VERSION 5.8 ;
BUSBITCHARS "[]" ;
DIVIDERCHAR "/" ;
CLEARANCEMEASURE EUCLIDEAN ;

SITE gt2_7t
    SIZE 0.0420 BY 0.1680 ;
    CLASS CORE ;
    SYMMETRY Y ;
END gt2_7t

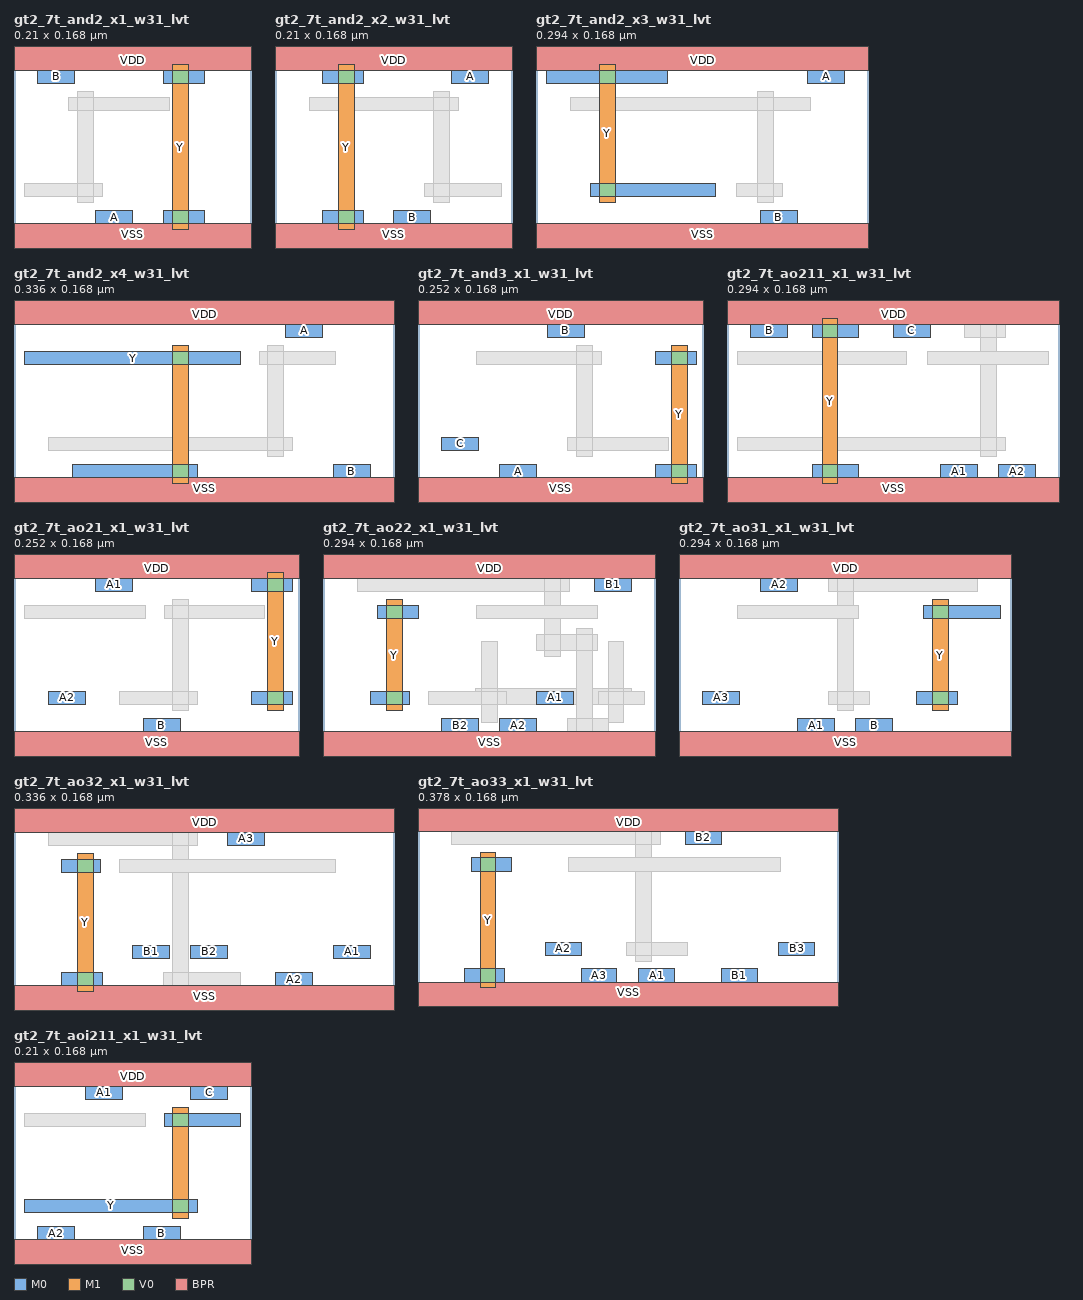
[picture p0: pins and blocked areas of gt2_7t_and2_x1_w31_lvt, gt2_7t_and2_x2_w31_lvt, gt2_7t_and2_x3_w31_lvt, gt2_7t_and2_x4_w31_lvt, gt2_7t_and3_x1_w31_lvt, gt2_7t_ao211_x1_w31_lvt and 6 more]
MACRO gt2_7t_and2_x1_w31_lvt
  CLASS CORE ;
  ORIGIN 0 0 ;
  FOREIGN gt2_6t_and2_x1_w31_lvt 0 0 ;
  SIZE 0.2100 BY 0.1680 ;
  SYMMETRY X Y ;
  SITE gt2_7t ;
  PIN A
    DIRECTION INPUT ;
    USE SIGNAL ;
    PORT
      LAYER M0 ;
        RECT 0.0725 0.0160 0.1050 0.0280 ;
    END
  END A
  PIN B
    DIRECTION INPUT ;
    USE SIGNAL ;
    PORT
      LAYER M0 ;
        RECT 0.0210 0.1400 0.0535 0.1520 ;
    END
  END B
  PIN Y
    DIRECTION OUTPUT ;
    USE SIGNAL ;
    PORT
      LAYER M1 ;
        RECT 0.1400 0.0110 0.1540 0.1570 ;
      LAYER M0 ;
        RECT 0.1320 0.0160 0.1680 0.0280 ;
        RECT 0.1320 0.1400 0.1680 0.1520 ;
      LAYER V0 ;
        RECT 0.1400 0.0160 0.1540 0.0280 ;
        RECT 0.1400 0.1400 0.1540 0.1520 ;
    END
  END Y
  PIN VDD
    DIRECTION INOUT ;
    USE POWER ;
    SHAPE ABUTMENT ;
    PORT
      LAYER BPR ;
        RECT 0.0000 0.1520 0.2100 0.1840 ;
    END
  END VDD
  PIN VSS
    DIRECTION INOUT ;
    USE GROUND ;
    SHAPE ABUTMENT ;
    PORT
      LAYER BPR ;
        RECT 0.0000 -0.0160 0.2100 0.0160 ;
    END
  END VSS
  OBS
    LAYER M1 ;
      RECT 0.0560 0.0350 0.0700 0.1330 ;
    LAYER M0 ;
      RECT 0.0095 0.0400 0.0780 0.0520 ;
      RECT 0.0480 0.1160 0.1375 0.1280 ;
    LAYER V0 ;
      RECT 0.0560 0.0400 0.0700 0.0520 ;
      RECT 0.0560 0.1160 0.0700 0.1280 ;
  END
END gt2_7t_and2_x1_w31_lvt

MACRO gt2_7t_and2_x2_w31_lvt
  CLASS CORE ;
  ORIGIN 0 0 ;
  FOREIGN gt2_6t_and2_x2_w31_lvt 0 0 ;
  SIZE 0.2100 BY 0.1680 ;
  SYMMETRY X Y ;
  SITE gt2_7t ;
  PIN A
    DIRECTION INPUT ;
    USE SIGNAL ;
    PORT
      LAYER M0 ;
        RECT 0.1565 0.1400 0.1890 0.1520 ;
    END
  END A
  PIN B
    DIRECTION INPUT ;
    USE SIGNAL ;
    PORT
      LAYER M0 ;
        RECT 0.1050 0.0160 0.1375 0.0280 ;
    END
  END B
  PIN Y
    DIRECTION OUTPUT ;
    USE SIGNAL ;
    PORT
      LAYER M1 ;
        RECT 0.0560 0.0110 0.0700 0.1570 ;
      LAYER M0 ;
        RECT 0.0420 0.0160 0.0780 0.0280 ;
        RECT 0.0420 0.1400 0.0780 0.1520 ;
      LAYER V0 ;
        RECT 0.0560 0.0160 0.0700 0.0280 ;
        RECT 0.0560 0.1400 0.0700 0.1520 ;
    END
  END Y
  PIN VDD
    DIRECTION INOUT ;
    USE POWER ;
    SHAPE ABUTMENT ;
    PORT
      LAYER BPR ;
        RECT 0.0000 0.1520 0.2100 0.1840 ;
    END
  END VDD
  PIN VSS
    DIRECTION INOUT ;
    USE GROUND ;
    SHAPE ABUTMENT ;
    PORT
      LAYER BPR ;
        RECT 0.0000 -0.0160 0.2100 0.0160 ;
    END
  END VSS
  OBS
    LAYER M1 ;
      RECT 0.1400 0.0350 0.1540 0.1330 ;
    LAYER M0 ;
      RECT 0.1320 0.0400 0.2005 0.0520 ;
      RECT 0.0305 0.1160 0.1620 0.1280 ;
    LAYER V0 ;
      RECT 0.1400 0.0400 0.1540 0.0520 ;
      RECT 0.1400 0.1160 0.1540 0.1280 ;
  END
END gt2_7t_and2_x2_w31_lvt

MACRO gt2_7t_and2_x3_w31_lvt
  CLASS CORE ;
  ORIGIN 0 0 ;
  FOREIGN gt2_6t_and2_x3_w31_lvt 0 0 ;
  SIZE 0.2940 BY 0.1680 ;
  SYMMETRY X Y ;
  SITE gt2_7t ;
  PIN A
    DIRECTION INPUT ;
    USE SIGNAL ;
    PORT
      LAYER M0 ;
        RECT 0.2405 0.1400 0.2730 0.1520 ;
    END
  END A
  PIN B
    DIRECTION INPUT ;
    USE SIGNAL ;
    PORT
      LAYER M0 ;
        RECT 0.1985 0.0160 0.2310 0.0280 ;
    END
  END B
  PIN Y
    DIRECTION OUTPUT ;
    USE SIGNAL ;
    PORT
      LAYER M1 ;
        RECT 0.0560 0.0350 0.0700 0.1570 ;
      LAYER M0 ;
        RECT 0.0480 0.0400 0.1585 0.0520 ;
        RECT 0.0095 0.1400 0.1165 0.1520 ;
      LAYER V0 ;
        RECT 0.0560 0.0400 0.0700 0.0520 ;
        RECT 0.0560 0.1400 0.0700 0.1520 ;
    END
  END Y
  PIN VDD
    DIRECTION INOUT ;
    USE POWER ;
    SHAPE ABUTMENT ;
    PORT
      LAYER BPR ;
        RECT 0.0000 0.1520 0.2940 0.1840 ;
    END
  END VDD
  PIN VSS
    DIRECTION INOUT ;
    USE GROUND ;
    SHAPE ABUTMENT ;
    PORT
      LAYER BPR ;
        RECT 0.0000 -0.0160 0.2940 0.0160 ;
    END
  END VSS
  OBS
    LAYER M1 ;
      RECT 0.1960 0.0350 0.2100 0.1330 ;
    LAYER M0 ;
      RECT 0.1775 0.0400 0.2180 0.0520 ;
      RECT 0.0305 0.1160 0.2425 0.1280 ;
    LAYER V0 ;
      RECT 0.1960 0.0400 0.2100 0.0520 ;
      RECT 0.1960 0.1160 0.2100 0.1280 ;
  END
END gt2_7t_and2_x3_w31_lvt

MACRO gt2_7t_and2_x4_w31_lvt
  CLASS CORE ;
  ORIGIN 0 0 ;
  FOREIGN gt2_6t_and2_x4_w31_lvt 0 0 ;
  SIZE 0.3360 BY 0.1680 ;
  SYMMETRY X Y ;
  SITE gt2_7t ;
  PIN A
    DIRECTION INPUT ;
    USE SIGNAL ;
    PORT
      LAYER M0 ;
        RECT 0.2405 0.1400 0.2730 0.1520 ;
    END
  END A
  PIN B
    DIRECTION INPUT ;
    USE SIGNAL ;
    PORT
      LAYER M0 ;
        RECT 0.2825 0.0160 0.3150 0.0280 ;
    END
  END B
  PIN Y
    DIRECTION OUTPUT ;
    USE SIGNAL ;
    PORT
      LAYER M1 ;
        RECT 0.1400 0.0110 0.1540 0.1330 ;
      LAYER M0 ;
        RECT 0.0515 0.0160 0.1620 0.0280 ;
        RECT 0.0095 0.1160 0.2005 0.1280 ;
      LAYER V0 ;
        RECT 0.1400 0.0160 0.1540 0.0280 ;
        RECT 0.1400 0.1160 0.1540 0.1280 ;
    END
  END Y
  PIN VDD
    DIRECTION INOUT ;
    USE POWER ;
    SHAPE ABUTMENT ;
    PORT
      LAYER BPR ;
        RECT 0.0000 0.1520 0.3360 0.1840 ;
    END
  END VDD
  PIN VSS
    DIRECTION INOUT ;
    USE GROUND ;
    SHAPE ABUTMENT ;
    PORT
      LAYER BPR ;
        RECT 0.0000 -0.0160 0.3360 0.0160 ;
    END
  END VSS
  OBS
    LAYER M1 ;
      RECT 0.2240 0.0350 0.2380 0.1330 ;
    LAYER M0 ;
      RECT 0.0305 0.0400 0.2460 0.0520 ;
      RECT 0.2175 0.1160 0.2845 0.1280 ;
    LAYER V0 ;
      RECT 0.2240 0.0400 0.2380 0.0520 ;
      RECT 0.2240 0.1160 0.2380 0.1280 ;
  END
END gt2_7t_and2_x4_w31_lvt

MACRO gt2_7t_and3_x1_w31_lvt
  CLASS CORE ;
  ORIGIN 0 0 ;
  FOREIGN gt2_6t_and3_x1_w31_lvt 0 0 ;
  SIZE 0.2520 BY 0.1680 ;
  SYMMETRY X Y ;
  SITE gt2_7t ;
  PIN A
    DIRECTION INPUT ;
    USE SIGNAL ;
    PORT
      LAYER M0 ;
        RECT 0.0725 0.0160 0.1050 0.0280 ;
    END
  END A
  PIN B
    DIRECTION INPUT ;
    USE SIGNAL ;
    PORT
      LAYER M0 ;
        RECT 0.1145 0.1400 0.1470 0.1520 ;
    END
  END B
  PIN C
    DIRECTION INPUT ;
    USE SIGNAL ;
    PORT
      LAYER M0 ;
        RECT 0.0210 0.0400 0.0535 0.0520 ;
    END
  END C
  PIN Y
    DIRECTION OUTPUT ;
    USE SIGNAL ;
    PORT
      LAYER M1 ;
        RECT 0.2240 0.0110 0.2380 0.1330 ;
      LAYER M0 ;
        RECT 0.2100 0.0160 0.2460 0.0280 ;
        RECT 0.2100 0.1160 0.2460 0.1280 ;
      LAYER V0 ;
        RECT 0.2240 0.0160 0.2380 0.0280 ;
        RECT 0.2240 0.1160 0.2380 0.1280 ;
    END
  END Y
  PIN VDD
    DIRECTION INOUT ;
    USE POWER ;
    SHAPE ABUTMENT ;
    PORT
      LAYER BPR ;
        RECT 0.0000 0.1520 0.2520 0.1840 ;
    END
  END VDD
  PIN VSS
    DIRECTION INOUT ;
    USE GROUND ;
    SHAPE ABUTMENT ;
    PORT
      LAYER BPR ;
        RECT 0.0000 -0.0160 0.2520 0.0160 ;
    END
  END VSS
  OBS
    LAYER M1 ;
      RECT 0.1400 0.0350 0.1540 0.1330 ;
    LAYER M0 ;
      RECT 0.1320 0.0400 0.2215 0.0520 ;
      RECT 0.0515 0.1160 0.1620 0.1280 ;
    LAYER V0 ;
      RECT 0.1400 0.0400 0.1540 0.0520 ;
      RECT 0.1400 0.1160 0.1540 0.1280 ;
  END
END gt2_7t_and3_x1_w31_lvt

MACRO gt2_7t_ao211_x1_w31_lvt
  CLASS CORE ;
  ORIGIN 0 0 ;
  FOREIGN gt2_6t_ao211_x1_w31_lvt 0 0 ;
  SIZE 0.2940 BY 0.1680 ;
  SYMMETRY X Y ;
  SITE gt2_7t ;
  PIN A1
    DIRECTION INPUT ;
    USE SIGNAL ;
    PORT
      LAYER M0 ;
        RECT 0.1890 0.0160 0.2215 0.0280 ;
    END
  END A1
  PIN A2
    DIRECTION INPUT ;
    USE SIGNAL ;
    PORT
      LAYER M0 ;
        RECT 0.2405 0.0160 0.2730 0.0280 ;
    END
  END A2
  PIN B
    DIRECTION INPUT ;
    USE SIGNAL ;
    PORT
      LAYER M0 ;
        RECT 0.0210 0.1400 0.0535 0.1520 ;
    END
  END B
  PIN C
    DIRECTION INPUT ;
    USE SIGNAL ;
    PORT
      LAYER M0 ;
        RECT 0.1470 0.1400 0.1795 0.1520 ;
    END
  END C
  PIN Y
    DIRECTION OUTPUT ;
    USE SIGNAL ;
    PORT
      LAYER M1 ;
        RECT 0.0840 0.0110 0.0980 0.1570 ;
      LAYER M0 ;
        RECT 0.0760 0.0160 0.1165 0.0280 ;
        RECT 0.0760 0.1400 0.1165 0.1520 ;
      LAYER V0 ;
        RECT 0.0840 0.0160 0.0980 0.0280 ;
        RECT 0.0840 0.1400 0.0980 0.1520 ;
    END
  END Y
  PIN VDD
    DIRECTION INOUT ;
    USE POWER ;
    SHAPE ABUTMENT ;
    PORT
      LAYER BPR ;
        RECT 0.0000 0.1520 0.2940 0.1840 ;
    END
  END VDD
  PIN VSS
    DIRECTION INOUT ;
    USE GROUND ;
    SHAPE ABUTMENT ;
    PORT
      LAYER BPR ;
        RECT 0.0000 -0.0160 0.2940 0.0160 ;
    END
  END VSS
  OBS
    LAYER M1 ;
      RECT 0.2240 0.0350 0.2380 0.1570 ;
    LAYER M0 ;
      RECT 0.0095 0.0400 0.2460 0.0520 ;
      RECT 0.2100 0.1400 0.2460 0.1520 ;
      RECT 0.0095 0.1160 0.1585 0.1280 ;
      RECT 0.1775 0.1160 0.2845 0.1280 ;
    LAYER V0 ;
      RECT 0.2240 0.0400 0.2380 0.0520 ;
      RECT 0.2240 0.1400 0.2380 0.1520 ;
  END
END gt2_7t_ao211_x1_w31_lvt

MACRO gt2_7t_ao21_x1_w31_lvt
  CLASS CORE ;
  ORIGIN 0 0 ;
  FOREIGN gt2_6t_ao21_x1_w31_lvt 0 0 ;
  SIZE 0.2520 BY 0.1680 ;
  SYMMETRY X Y ;
  SITE gt2_7t ;
  PIN A1
    DIRECTION INPUT ;
    USE SIGNAL ;
    PORT
      LAYER M0 ;
        RECT 0.0725 0.1400 0.1050 0.1520 ;
    END
  END A1
  PIN A2
    DIRECTION INPUT ;
    USE SIGNAL ;
    PORT
      LAYER M0 ;
        RECT 0.0305 0.0400 0.0630 0.0520 ;
    END
  END A2
  PIN B
    DIRECTION INPUT ;
    USE SIGNAL ;
    PORT
      LAYER M0 ;
        RECT 0.1145 0.0160 0.1470 0.0280 ;
    END
  END B
  PIN Y
    DIRECTION OUTPUT ;
    USE SIGNAL ;
    PORT
      LAYER M1 ;
        RECT 0.2240 0.0350 0.2380 0.1570 ;
      LAYER M0 ;
        RECT 0.2100 0.0400 0.2460 0.0520 ;
        RECT 0.2100 0.1400 0.2460 0.1520 ;
      LAYER V0 ;
        RECT 0.2240 0.0400 0.2380 0.0520 ;
        RECT 0.2240 0.1400 0.2380 0.1520 ;
    END
  END Y
  PIN VDD
    DIRECTION INOUT ;
    USE POWER ;
    SHAPE ABUTMENT ;
    PORT
      LAYER BPR ;
        RECT 0.0000 0.1520 0.2520 0.1840 ;
    END
  END VDD
  PIN VSS
    DIRECTION INOUT ;
    USE GROUND ;
    SHAPE ABUTMENT ;
    PORT
      LAYER BPR ;
        RECT 0.0000 -0.0160 0.2520 0.0160 ;
    END
  END VSS
  OBS
    LAYER M1 ;
      RECT 0.1400 0.0350 0.1540 0.1330 ;
    LAYER M0 ;
      RECT 0.0095 0.1160 0.1165 0.1280 ;
      RECT 0.0935 0.0400 0.1620 0.0520 ;
      RECT 0.1335 0.1160 0.2215 0.1280 ;
    LAYER V0 ;
      RECT 0.1400 0.0400 0.1540 0.0520 ;
      RECT 0.1400 0.1160 0.1540 0.1280 ;
  END
END gt2_7t_ao21_x1_w31_lvt

MACRO gt2_7t_ao22_x1_w31_lvt
  CLASS CORE ;
  ORIGIN 0 0 ;
  FOREIGN gt2_6t_ao22_x1_w31_lvt 0 0 ;
  SIZE 0.2940 BY 0.1680 ;
  SYMMETRY X Y ;
  SITE gt2_7t ;
  PIN A1
    DIRECTION INPUT ;
    USE SIGNAL ;
    PORT
      LAYER M0 ;
        RECT 0.1890 0.0400 0.2215 0.0520 ;
    END
  END A1
  PIN A2
    DIRECTION INPUT ;
    USE SIGNAL ;
    PORT
      LAYER M0 ;
        RECT 0.1565 0.0160 0.1890 0.0280 ;
    END
  END A2
  PIN B1
    DIRECTION INPUT ;
    USE SIGNAL ;
    PORT
      LAYER M0 ;
        RECT 0.2405 0.1400 0.2730 0.1520 ;
    END
  END B1
  PIN B2
    DIRECTION INPUT ;
    USE SIGNAL ;
    PORT
      LAYER M0 ;
        RECT 0.1050 0.0160 0.1375 0.0280 ;
    END
  END B2
  PIN Y
    DIRECTION OUTPUT ;
    USE SIGNAL ;
    PORT
      LAYER M1 ;
        RECT 0.0560 0.0350 0.0700 0.1330 ;
      LAYER M0 ;
        RECT 0.0420 0.0400 0.0765 0.0520 ;
        RECT 0.0480 0.1160 0.0840 0.1280 ;
      LAYER V0 ;
        RECT 0.0560 0.0400 0.0700 0.0520 ;
        RECT 0.0560 0.1160 0.0700 0.1280 ;
    END
  END Y
  PIN VDD
    DIRECTION INOUT ;
    USE POWER ;
    SHAPE ABUTMENT ;
    PORT
      LAYER BPR ;
        RECT 0.0000 0.1520 0.2940 0.1840 ;
    END
  END VDD
  PIN VSS
    DIRECTION INOUT ;
    USE GROUND ;
    SHAPE ABUTMENT ;
    PORT
      LAYER BPR ;
        RECT 0.0000 -0.0160 0.2940 0.0160 ;
    END
  END VSS
  OBS
    LAYER M2 ;
      RECT 0.1890 0.0880 0.2430 0.1020 ;
      RECT 0.1350 0.0400 0.2730 0.0540 ;
    LAYER M1 ;
      RECT 0.2240 0.0110 0.2380 0.1070 ;
      RECT 0.1960 0.0830 0.2100 0.1570 ;
      RECT 0.1400 0.0240 0.1540 0.0960 ;
      RECT 0.2520 0.0240 0.2660 0.0960 ;
    LAYER M0 ;
      RECT 0.2160 0.0160 0.2520 0.0280 ;
      RECT 0.0305 0.1400 0.2180 0.1520 ;
      RECT 0.0935 0.0400 0.1620 0.0520 ;
      RECT 0.2440 0.0400 0.2845 0.0520 ;
      RECT 0.1355 0.1160 0.2425 0.1280 ;
    LAYER V1 ;
      RECT 0.1960 0.0880 0.2100 0.1020 ;
      RECT 0.2240 0.0880 0.2380 0.1020 ;
      RECT 0.1400 0.0400 0.1540 0.0540 ;
      RECT 0.2520 0.0400 0.2660 0.0540 ;
    LAYER V0 ;
      RECT 0.2240 0.0160 0.2380 0.0280 ;
      RECT 0.1960 0.1400 0.2100 0.1520 ;
      RECT 0.1400 0.0400 0.1540 0.0520 ;
      RECT 0.2520 0.0400 0.2660 0.0520 ;
  END
END gt2_7t_ao22_x1_w31_lvt

MACRO gt2_7t_ao31_x1_w31_lvt
  CLASS CORE ;
  ORIGIN 0 0 ;
  FOREIGN gt2_6t_ao31_x1_w31_lvt 0 0 ;
  SIZE 0.2940 BY 0.1680 ;
  SYMMETRY X Y ;
  SITE gt2_7t ;
  PIN A1
    DIRECTION INPUT ;
    USE SIGNAL ;
    PORT
      LAYER M0 ;
        RECT 0.1050 0.0160 0.1375 0.0280 ;
    END
  END A1
  PIN A2
    DIRECTION INPUT ;
    USE SIGNAL ;
    PORT
      LAYER M0 ;
        RECT 0.0725 0.1400 0.1050 0.1520 ;
    END
  END A2
  PIN A3
    DIRECTION INPUT ;
    USE SIGNAL ;
    PORT
      LAYER M0 ;
        RECT 0.0210 0.0400 0.0535 0.0520 ;
    END
  END A3
  PIN B
    DIRECTION INPUT ;
    USE SIGNAL ;
    PORT
      LAYER M0 ;
        RECT 0.1565 0.0160 0.1890 0.0280 ;
    END
  END B
  PIN Y
    DIRECTION OUTPUT ;
    USE SIGNAL ;
    PORT
      LAYER M1 ;
        RECT 0.2240 0.0350 0.2380 0.1330 ;
      LAYER M0 ;
        RECT 0.2100 0.0400 0.2460 0.0520 ;
        RECT 0.2160 0.1160 0.2845 0.1280 ;
      LAYER V0 ;
        RECT 0.2240 0.0400 0.2380 0.0520 ;
        RECT 0.2240 0.1160 0.2380 0.1280 ;
    END
  END Y
  PIN VDD
    DIRECTION INOUT ;
    USE POWER ;
    SHAPE ABUTMENT ;
    PORT
      LAYER BPR ;
        RECT 0.0000 0.1520 0.2940 0.1840 ;
    END
  END VDD
  PIN VSS
    DIRECTION INOUT ;
    USE GROUND ;
    SHAPE ABUTMENT ;
    PORT
      LAYER BPR ;
        RECT 0.0000 -0.0160 0.2940 0.0160 ;
    END
  END VSS
  OBS
    LAYER M1 ;
      RECT 0.1400 0.0350 0.1540 0.1570 ;
    LAYER M0 ;
      RECT 0.0515 0.1160 0.1585 0.1280 ;
      RECT 0.1320 0.0400 0.1680 0.0520 ;
      RECT 0.1320 0.1400 0.2635 0.1520 ;
    LAYER V0 ;
      RECT 0.1400 0.0400 0.1540 0.0520 ;
      RECT 0.1400 0.1400 0.1540 0.1520 ;
  END
END gt2_7t_ao31_x1_w31_lvt

MACRO gt2_7t_ao32_x1_w31_lvt
  CLASS CORE ;
  ORIGIN 0 0 ;
  FOREIGN gt2_6t_ao32_x1_w31_lvt 0 0 ;
  SIZE 0.3360 BY 0.1680 ;
  SYMMETRY X Y ;
  SITE gt2_7t ;
  PIN A1
    DIRECTION INPUT ;
    USE SIGNAL ;
    PORT
      LAYER M0 ;
        RECT 0.2825 0.0400 0.3150 0.0520 ;
    END
  END A1
  PIN A2
    DIRECTION INPUT ;
    USE SIGNAL ;
    PORT
      LAYER M0 ;
        RECT 0.2310 0.0160 0.2635 0.0280 ;
    END
  END A2
  PIN A3
    DIRECTION INPUT ;
    USE SIGNAL ;
    PORT
      LAYER M0 ;
        RECT 0.1890 0.1400 0.2215 0.1520 ;
    END
  END A3
  PIN B1
    DIRECTION INPUT ;
    USE SIGNAL ;
    PORT
      LAYER M0 ;
        RECT 0.1050 0.0400 0.1375 0.0520 ;
    END
  END B1
  PIN B2
    DIRECTION INPUT ;
    USE SIGNAL ;
    PORT
      LAYER M0 ;
        RECT 0.1565 0.0400 0.1890 0.0520 ;
    END
  END B2
  PIN Y
    DIRECTION OUTPUT ;
    USE SIGNAL ;
    PORT
      LAYER M1 ;
        RECT 0.0560 0.0110 0.0700 0.1330 ;
      LAYER M0 ;
        RECT 0.0420 0.0160 0.0780 0.0280 ;
        RECT 0.0420 0.1160 0.0765 0.1280 ;
      LAYER V0 ;
        RECT 0.0560 0.0160 0.0700 0.0280 ;
        RECT 0.0560 0.1160 0.0700 0.1280 ;
    END
  END Y
  PIN VDD
    DIRECTION INOUT ;
    USE POWER ;
    SHAPE ABUTMENT ;
    PORT
      LAYER BPR ;
        RECT 0.0000 0.1520 0.3360 0.1840 ;
    END
  END VDD
  PIN VSS
    DIRECTION INOUT ;
    USE GROUND ;
    SHAPE ABUTMENT ;
    PORT
      LAYER BPR ;
        RECT 0.0000 -0.0160 0.3360 0.0160 ;
    END
  END VSS
  OBS
    LAYER M1 ;
      RECT 0.1400 0.0110 0.1540 0.1570 ;
    LAYER M0 ;
      RECT 0.1320 0.0160 0.2005 0.0280 ;
      RECT 0.0305 0.1400 0.1620 0.1520 ;
      RECT 0.0935 0.1160 0.2845 0.1280 ;
    LAYER V0 ;
      RECT 0.1400 0.0160 0.1540 0.0280 ;
      RECT 0.1400 0.1400 0.1540 0.1520 ;
  END
END gt2_7t_ao32_x1_w31_lvt

MACRO gt2_7t_ao33_x1_w31_lvt
  CLASS CORE ;
  ORIGIN 0 0 ;
  FOREIGN gt2_6t_ao33_x1_w31_lvt 0 0 ;
  SIZE 0.3780 BY 0.1680 ;
  SYMMETRY X Y ;
  SITE gt2_7t ;
  PIN A1
    DIRECTION INPUT ;
    USE SIGNAL ;
    PORT
      LAYER M0 ;
        RECT 0.1985 0.0160 0.2310 0.0280 ;
    END
  END A1
  PIN A2
    DIRECTION INPUT ;
    USE SIGNAL ;
    PORT
      LAYER M0 ;
        RECT 0.1145 0.0400 0.1470 0.0520 ;
    END
  END A2
  PIN A3
    DIRECTION INPUT ;
    USE SIGNAL ;
    PORT
      LAYER M0 ;
        RECT 0.1470 0.0160 0.1790 0.0280 ;
    END
  END A3
  PIN B1
    DIRECTION INPUT ;
    USE SIGNAL ;
    PORT
      LAYER M0 ;
        RECT 0.2730 0.0160 0.3055 0.0280 ;
    END
  END B1
  PIN B2
    DIRECTION INPUT ;
    USE SIGNAL ;
    PORT
      LAYER M0 ;
        RECT 0.2405 0.1400 0.2730 0.1520 ;
    END
  END B2
  PIN B3
    DIRECTION INPUT ;
    USE SIGNAL ;
    PORT
      LAYER M0 ;
        RECT 0.3245 0.0400 0.3570 0.0520 ;
    END
  END B3
  PIN Y
    DIRECTION OUTPUT ;
    USE SIGNAL ;
    PORT
      LAYER M1 ;
        RECT 0.0560 0.0110 0.0700 0.1330 ;
      LAYER M0 ;
        RECT 0.0420 0.0160 0.0780 0.0280 ;
        RECT 0.0480 0.1160 0.0840 0.1280 ;
      LAYER V0 ;
        RECT 0.0560 0.0160 0.0700 0.0280 ;
        RECT 0.0560 0.1160 0.0700 0.1280 ;
    END
  END Y
  PIN VDD
    DIRECTION INOUT ;
    USE POWER ;
    SHAPE ABUTMENT ;
    PORT
      LAYER BPR ;
        RECT 0.0000 0.1520 0.3780 0.1840 ;
    END
  END VDD
  PIN VSS
    DIRECTION INOUT ;
    USE GROUND ;
    SHAPE ABUTMENT ;
    PORT
      LAYER BPR ;
        RECT 0.0000 -0.0160 0.3780 0.0160 ;
    END
  END VSS
  OBS
    LAYER M1 ;
      RECT 0.1960 0.0350 0.2100 0.1570 ;
    LAYER M0 ;
      RECT 0.1355 0.1160 0.3265 0.1280 ;
      RECT 0.1880 0.0400 0.2425 0.0520 ;
      RECT 0.0305 0.1400 0.2180 0.1520 ;
    LAYER V0 ;
      RECT 0.1960 0.0400 0.2100 0.0520 ;
      RECT 0.1960 0.1400 0.2100 0.1520 ;
  END
END gt2_7t_ao33_x1_w31_lvt

MACRO gt2_7t_aoi211_x1_w31_lvt
  CLASS CORE ;
  ORIGIN 0 0 ;
  FOREIGN gt2_6t_aoi211_x1_w31_lvt 0 0 ;
  SIZE 0.2100 BY 0.1680 ;
  SYMMETRY X Y ;
  SITE gt2_7t ;
  PIN A1
    DIRECTION INPUT ;
    USE SIGNAL ;
    PORT
      LAYER M0 ;
        RECT 0.0630 0.1400 0.0955 0.1520 ;
    END
  END A1
  PIN A2
    DIRECTION INPUT ;
    USE SIGNAL ;
    PORT
      LAYER M0 ;
        RECT 0.0210 0.0160 0.0535 0.0280 ;
    END
  END A2
  PIN B
    DIRECTION INPUT ;
    USE SIGNAL ;
    PORT
      LAYER M0 ;
        RECT 0.1145 0.0160 0.1470 0.0280 ;
    END
  END B
  PIN C
    DIRECTION INPUT ;
    USE SIGNAL ;
    PORT
      LAYER M0 ;
        RECT 0.1565 0.1400 0.1890 0.1520 ;
    END
  END C
  PIN Y
    DIRECTION OUTPUT ;
    USE SIGNAL ;
    PORT
      LAYER M1 ;
        RECT 0.1400 0.0350 0.1540 0.1330 ;
      LAYER M0 ;
        RECT 0.0095 0.0400 0.1620 0.0520 ;
        RECT 0.1335 0.1160 0.2005 0.1280 ;
      LAYER V0 ;
        RECT 0.1400 0.0400 0.1540 0.0520 ;
        RECT 0.1400 0.1160 0.1540 0.1280 ;
    END
  END Y
  PIN VDD
    DIRECTION INOUT ;
    USE POWER ;
    SHAPE ABUTMENT ;
    PORT
      LAYER BPR ;
        RECT 0.0000 0.1520 0.2100 0.1840 ;
    END
  END VDD
  PIN VSS
    DIRECTION INOUT ;
    USE GROUND ;
    SHAPE ABUTMENT ;
    PORT
      LAYER BPR ;
        RECT 0.0000 -0.0160 0.2100 0.0160 ;
    END
  END VSS
  OBS
    LAYER M0 ;
      RECT 0.0095 0.1160 0.1165 0.1280 ;
  END
END gt2_7t_aoi211_x1_w31_lvt

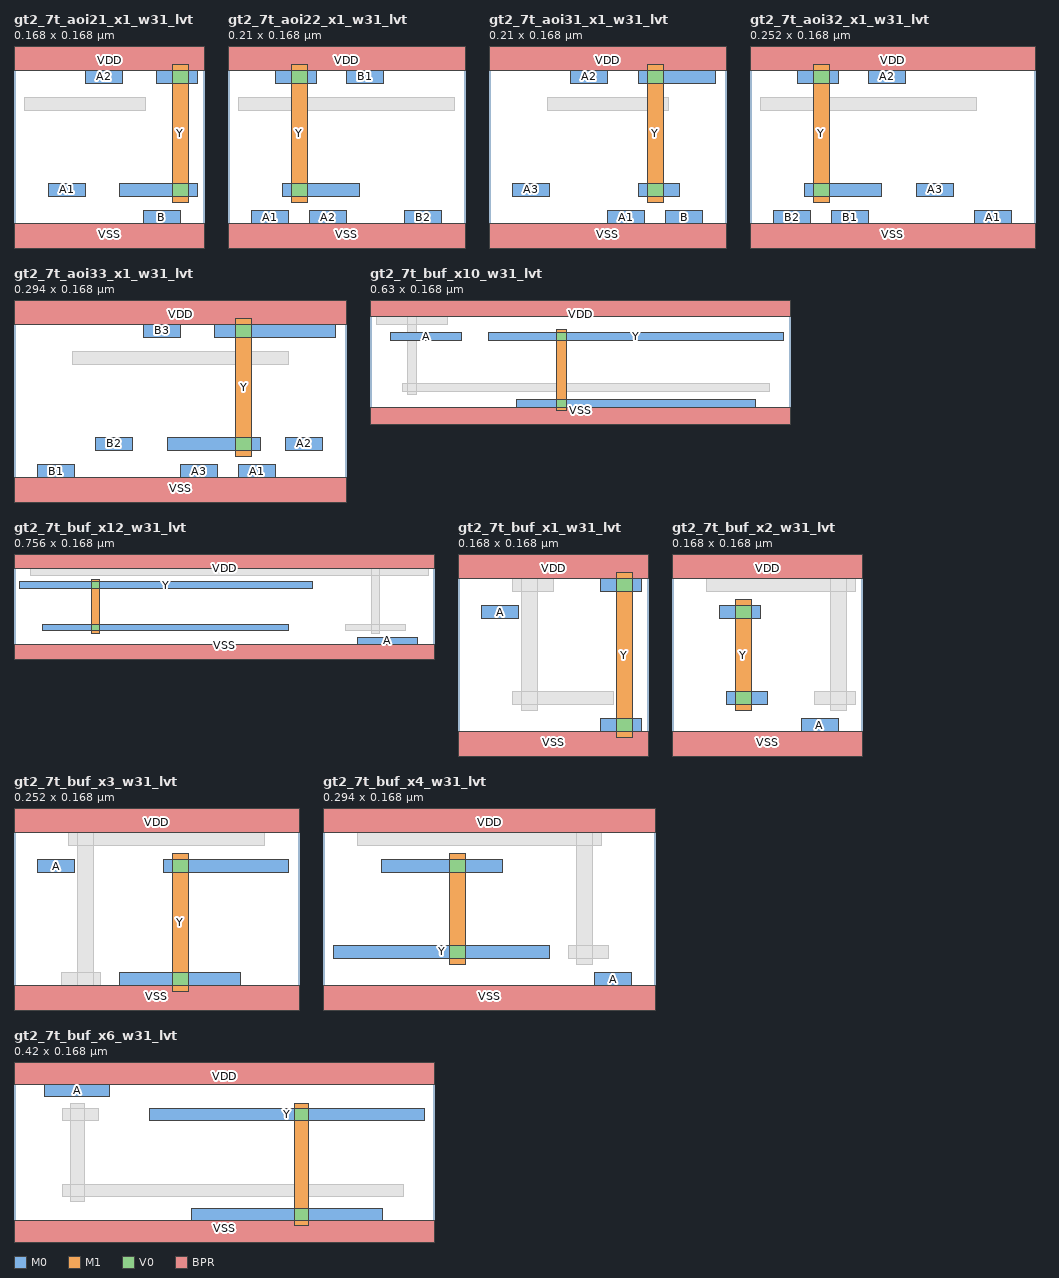
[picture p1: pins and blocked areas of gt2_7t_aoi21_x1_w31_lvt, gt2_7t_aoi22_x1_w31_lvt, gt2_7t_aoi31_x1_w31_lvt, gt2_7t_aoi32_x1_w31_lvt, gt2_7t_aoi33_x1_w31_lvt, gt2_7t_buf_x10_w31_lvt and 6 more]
MACRO gt2_7t_aoi21_x1_w31_lvt
  CLASS CORE ;
  ORIGIN 0 0 ;
  FOREIGN gt2_6t_aoi21_x1_w31_lvt 0 0 ;
  SIZE 0.1680 BY 0.1680 ;
  SYMMETRY X Y ;
  SITE gt2_7t ;
  PIN A1
    DIRECTION INPUT ;
    USE SIGNAL ;
    PORT
      LAYER M0 ;
        RECT 0.0305 0.0400 0.0630 0.0520 ;
    END
  END A1
  PIN A2
    DIRECTION INPUT ;
    USE SIGNAL ;
    PORT
      LAYER M0 ;
        RECT 0.0630 0.1400 0.0955 0.1520 ;
    END
  END A2
  PIN B
    DIRECTION INPUT ;
    USE SIGNAL ;
    PORT
      LAYER M0 ;
        RECT 0.1145 0.0160 0.1470 0.0280 ;
    END
  END B
  PIN Y
    DIRECTION OUTPUT ;
    USE SIGNAL ;
    PORT
      LAYER M1 ;
        RECT 0.1400 0.0350 0.1540 0.1570 ;
      LAYER M0 ;
        RECT 0.0935 0.0400 0.1620 0.0520 ;
        RECT 0.1260 0.1400 0.1620 0.1520 ;
      LAYER V0 ;
        RECT 0.1400 0.0400 0.1540 0.0520 ;
        RECT 0.1400 0.1400 0.1540 0.1520 ;
    END
  END Y
  PIN VDD
    DIRECTION INOUT ;
    USE POWER ;
    SHAPE ABUTMENT ;
    PORT
      LAYER BPR ;
        RECT 0.0000 0.1520 0.1680 0.1840 ;
    END
  END VDD
  PIN VSS
    DIRECTION INOUT ;
    USE GROUND ;
    SHAPE ABUTMENT ;
    PORT
      LAYER BPR ;
        RECT 0.0000 -0.0160 0.1680 0.0160 ;
    END
  END VSS
  OBS
    LAYER M0 ;
      RECT 0.0095 0.1160 0.1165 0.1280 ;
  END
END gt2_7t_aoi21_x1_w31_lvt

MACRO gt2_7t_aoi22_x1_w31_lvt
  CLASS CORE ;
  ORIGIN 0 0 ;
  FOREIGN gt2_6t_aoi22_x1_w31_lvt 0 0 ;
  SIZE 0.2100 BY 0.1680 ;
  SYMMETRY X Y ;
  SITE gt2_7t ;
  PIN A1
    DIRECTION INPUT ;
    USE SIGNAL ;
    PORT
      LAYER M0 ;
        RECT 0.0210 0.0160 0.0535 0.0280 ;
    END
  END A1
  PIN A2
    DIRECTION INPUT ;
    USE SIGNAL ;
    PORT
      LAYER M0 ;
        RECT 0.0725 0.0160 0.1050 0.0280 ;
    END
  END A2
  PIN B1
    DIRECTION INPUT ;
    USE SIGNAL ;
    PORT
      LAYER M0 ;
        RECT 0.1050 0.1400 0.1375 0.1520 ;
    END
  END B1
  PIN B2
    DIRECTION INPUT ;
    USE SIGNAL ;
    PORT
      LAYER M0 ;
        RECT 0.1565 0.0160 0.1890 0.0280 ;
    END
  END B2
  PIN Y
    DIRECTION OUTPUT ;
    USE SIGNAL ;
    PORT
      LAYER M1 ;
        RECT 0.0560 0.0350 0.0700 0.1570 ;
      LAYER M0 ;
        RECT 0.0480 0.0400 0.1165 0.0520 ;
        RECT 0.0420 0.1400 0.0780 0.1520 ;
      LAYER V0 ;
        RECT 0.0560 0.0400 0.0700 0.0520 ;
        RECT 0.0560 0.1400 0.0700 0.1520 ;
    END
  END Y
  PIN VDD
    DIRECTION INOUT ;
    USE POWER ;
    SHAPE ABUTMENT ;
    PORT
      LAYER BPR ;
        RECT 0.0000 0.1520 0.2100 0.1840 ;
    END
  END VDD
  PIN VSS
    DIRECTION INOUT ;
    USE GROUND ;
    SHAPE ABUTMENT ;
    PORT
      LAYER BPR ;
        RECT 0.0000 -0.0160 0.2100 0.0160 ;
    END
  END VSS
  OBS
    LAYER M0 ;
      RECT 0.0095 0.1160 0.2005 0.1280 ;
  END
END gt2_7t_aoi22_x1_w31_lvt

MACRO gt2_7t_aoi31_x1_w31_lvt
  CLASS CORE ;
  ORIGIN 0 0 ;
  FOREIGN gt2_6t_aoi31_x1_w31_lvt 0 0 ;
  SIZE 0.2100 BY 0.1680 ;
  SYMMETRY X Y ;
  SITE gt2_7t ;
  PIN A1
    DIRECTION INPUT ;
    USE SIGNAL ;
    PORT
      LAYER M0 ;
        RECT 0.1050 0.0160 0.1375 0.0280 ;
    END
  END A1
  PIN A2
    DIRECTION INPUT ;
    USE SIGNAL ;
    PORT
      LAYER M0 ;
        RECT 0.0725 0.1400 0.1050 0.1520 ;
    END
  END A2
  PIN A3
    DIRECTION INPUT ;
    USE SIGNAL ;
    PORT
      LAYER M0 ;
        RECT 0.0210 0.0400 0.0535 0.0520 ;
    END
  END A3
  PIN B
    DIRECTION INPUT ;
    USE SIGNAL ;
    PORT
      LAYER M0 ;
        RECT 0.1565 0.0160 0.1890 0.0280 ;
    END
  END B
  PIN Y
    DIRECTION OUTPUT ;
    USE SIGNAL ;
    PORT
      LAYER M1 ;
        RECT 0.1400 0.0350 0.1540 0.1570 ;
      LAYER M0 ;
        RECT 0.1320 0.0400 0.1680 0.0520 ;
        RECT 0.1320 0.1400 0.2005 0.1520 ;
      LAYER V0 ;
        RECT 0.1400 0.0400 0.1540 0.0520 ;
        RECT 0.1400 0.1400 0.1540 0.1520 ;
    END
  END Y
  PIN VDD
    DIRECTION INOUT ;
    USE POWER ;
    SHAPE ABUTMENT ;
    PORT
      LAYER BPR ;
        RECT 0.0000 0.1520 0.2100 0.1840 ;
    END
  END VDD
  PIN VSS
    DIRECTION INOUT ;
    USE GROUND ;
    SHAPE ABUTMENT ;
    PORT
      LAYER BPR ;
        RECT 0.0000 -0.0160 0.2100 0.0160 ;
    END
  END VSS
  OBS
    LAYER M0 ;
      RECT 0.0515 0.1160 0.1585 0.1280 ;
  END
END gt2_7t_aoi31_x1_w31_lvt

MACRO gt2_7t_aoi32_x1_w31_lvt
  CLASS CORE ;
  ORIGIN 0 0 ;
  FOREIGN gt2_6t_aoi32_x1_w31_lvt 0 0 ;
  SIZE 0.2520 BY 0.1680 ;
  SYMMETRY X Y ;
  SITE gt2_7t ;
  PIN A1
    DIRECTION INPUT ;
    USE SIGNAL ;
    PORT
      LAYER M0 ;
        RECT 0.1985 0.0160 0.2310 0.0280 ;
    END
  END A1
  PIN A2
    DIRECTION INPUT ;
    USE SIGNAL ;
    PORT
      LAYER M0 ;
        RECT 0.1050 0.1400 0.1375 0.1520 ;
    END
  END A2
  PIN A3
    DIRECTION INPUT ;
    USE SIGNAL ;
    PORT
      LAYER M0 ;
        RECT 0.1470 0.0400 0.1795 0.0520 ;
    END
  END A3
  PIN B1
    DIRECTION INPUT ;
    USE SIGNAL ;
    PORT
      LAYER M0 ;
        RECT 0.0725 0.0160 0.1050 0.0280 ;
    END
  END B1
  PIN B2
    DIRECTION INPUT ;
    USE SIGNAL ;
    PORT
      LAYER M0 ;
        RECT 0.0210 0.0160 0.0535 0.0280 ;
    END
  END B2
  PIN Y
    DIRECTION OUTPUT ;
    USE SIGNAL ;
    PORT
      LAYER M1 ;
        RECT 0.0560 0.0350 0.0700 0.1570 ;
      LAYER M0 ;
        RECT 0.0480 0.0400 0.1165 0.0520 ;
        RECT 0.0420 0.1400 0.0780 0.1520 ;
      LAYER V0 ;
        RECT 0.0560 0.0400 0.0700 0.0520 ;
        RECT 0.0560 0.1400 0.0700 0.1520 ;
    END
  END Y
  PIN VDD
    DIRECTION INOUT ;
    USE POWER ;
    SHAPE ABUTMENT ;
    PORT
      LAYER BPR ;
        RECT 0.0000 0.1520 0.2520 0.1840 ;
    END
  END VDD
  PIN VSS
    DIRECTION INOUT ;
    USE GROUND ;
    SHAPE ABUTMENT ;
    PORT
      LAYER BPR ;
        RECT 0.0000 -0.0160 0.2520 0.0160 ;
    END
  END VSS
  OBS
    LAYER M0 ;
      RECT 0.0095 0.1160 0.2005 0.1280 ;
  END
END gt2_7t_aoi32_x1_w31_lvt

MACRO gt2_7t_aoi33_x1_w31_lvt
  CLASS CORE ;
  ORIGIN 0 0 ;
  FOREIGN gt2_6t_aoi33_x1_w31_lvt 0 0 ;
  SIZE 0.2940 BY 0.1680 ;
  SYMMETRY X Y ;
  SITE gt2_7t ;
  PIN A1
    DIRECTION INPUT ;
    USE SIGNAL ;
    PORT
      LAYER M0 ;
        RECT 0.1985 0.0160 0.2310 0.0280 ;
    END
  END A1
  PIN A2
    DIRECTION INPUT ;
    USE SIGNAL ;
    PORT
      LAYER M0 ;
        RECT 0.2405 0.0400 0.2730 0.0520 ;
    END
  END A2
  PIN A3
    DIRECTION INPUT ;
    USE SIGNAL ;
    PORT
      LAYER M0 ;
        RECT 0.1470 0.0160 0.1795 0.0280 ;
    END
  END A3
  PIN B1
    DIRECTION INPUT ;
    USE SIGNAL ;
    PORT
      LAYER M0 ;
        RECT 0.0210 0.0160 0.0535 0.0280 ;
    END
  END B1
  PIN B2
    DIRECTION INPUT ;
    USE SIGNAL ;
    PORT
      LAYER M0 ;
        RECT 0.0725 0.0400 0.1050 0.0520 ;
    END
  END B2
  PIN B3
    DIRECTION INPUT ;
    USE SIGNAL ;
    PORT
      LAYER M0 ;
        RECT 0.1145 0.1400 0.1470 0.1520 ;
    END
  END B3
  PIN Y
    DIRECTION OUTPUT ;
    USE SIGNAL ;
    PORT
      LAYER M1 ;
        RECT 0.1960 0.0350 0.2100 0.1570 ;
      LAYER M0 ;
        RECT 0.1355 0.0400 0.2180 0.0520 ;
        RECT 0.1775 0.1400 0.2845 0.1520 ;
      LAYER V0 ;
        RECT 0.1960 0.0400 0.2100 0.0520 ;
        RECT 0.1960 0.1400 0.2100 0.1520 ;
    END
  END Y
  PIN VDD
    DIRECTION INOUT ;
    USE POWER ;
    SHAPE ABUTMENT ;
    PORT
      LAYER BPR ;
        RECT 0.0000 0.1520 0.2940 0.1840 ;
    END
  END VDD
  PIN VSS
    DIRECTION INOUT ;
    USE GROUND ;
    SHAPE ABUTMENT ;
    PORT
      LAYER BPR ;
        RECT 0.0000 -0.0160 0.2940 0.0160 ;
    END
  END VSS
  OBS
    LAYER M0 ;
      RECT 0.0515 0.1160 0.2425 0.1280 ;
  END
END gt2_7t_aoi33_x1_w31_lvt

MACRO gt2_7t_buf_x10_w31_lvt
  CLASS CORE ;
  ORIGIN 0 0 ;
  FOREIGN gt2_6t_buf_x10_w31_lvt 0 0 ;
  SIZE 0.6300 BY 0.1680 ;
  SYMMETRY X Y ;
  SITE gt2_7t ;
  PIN A
    DIRECTION INPUT ;
    USE SIGNAL ;
    PORT
      LAYER M0 ;
        RECT 0.0305 0.1160 0.1375 0.1280 ;
    END
  END A
  PIN Y
    DIRECTION OUTPUT ;
    USE SIGNAL ;
    PORT
      LAYER M1 ;
        RECT 0.2800 0.0110 0.2940 0.1330 ;
      LAYER M0 ;
        RECT 0.2195 0.0160 0.5785 0.0280 ;
        RECT 0.1775 0.1160 0.6205 0.1280 ;
      LAYER V0 ;
        RECT 0.2800 0.0160 0.2940 0.0280 ;
        RECT 0.2800 0.1160 0.2940 0.1280 ;
    END
  END Y
  PIN VDD
    DIRECTION INOUT ;
    USE POWER ;
    SHAPE ABUTMENT ;
    PORT
      LAYER BPR ;
        RECT 0.0000 0.1520 0.6300 0.1840 ;
    END
  END VDD
  PIN VSS
    DIRECTION INOUT ;
    USE GROUND ;
    SHAPE ABUTMENT ;
    PORT
      LAYER BPR ;
        RECT 0.0000 -0.0160 0.6300 0.0160 ;
    END
  END VSS
  OBS
    LAYER M1 ;
      RECT 0.0560 0.0350 0.0700 0.1570 ;
    LAYER M0 ;
      RECT 0.0480 0.0400 0.5995 0.0520 ;
      RECT 0.0095 0.1400 0.1165 0.1520 ;
    LAYER V0 ;
      RECT 0.0560 0.0400 0.0700 0.0520 ;
      RECT 0.0560 0.1400 0.0700 0.1520 ;
  END
END gt2_7t_buf_x10_w31_lvt

MACRO gt2_7t_buf_x12_w31_lvt
  CLASS CORE ;
  ORIGIN 0 0 ;
  FOREIGN gt2_6t_buf_x12_w31_lvt 0 0 ;
  SIZE 0.7560 BY 0.1680 ;
  SYMMETRY X Y ;
  SITE gt2_7t ;
  PIN A
    DIRECTION INPUT ;
    USE SIGNAL ;
    PORT
      LAYER M0 ;
        RECT 0.6185 0.0160 0.7255 0.0280 ;
    END
  END A
  PIN Y
    DIRECTION OUTPUT ;
    USE SIGNAL ;
    PORT
      LAYER M1 ;
        RECT 0.1400 0.0350 0.1540 0.1330 ;
      LAYER M0 ;
        RECT 0.0515 0.0400 0.4945 0.0520 ;
        RECT 0.0095 0.1160 0.5365 0.1280 ;
      LAYER V0 ;
        RECT 0.1400 0.0400 0.1540 0.0520 ;
        RECT 0.1400 0.1160 0.1540 0.1280 ;
    END
  END Y
  PIN VDD
    DIRECTION INOUT ;
    USE POWER ;
    SHAPE ABUTMENT ;
    PORT
      LAYER BPR ;
        RECT 0.0000 0.1520 0.7560 0.1840 ;
    END
  END VDD
  PIN VSS
    DIRECTION INOUT ;
    USE GROUND ;
    SHAPE ABUTMENT ;
    PORT
      LAYER BPR ;
        RECT 0.0000 -0.0160 0.7560 0.0160 ;
    END
  END VSS
  OBS
    LAYER M1 ;
      RECT 0.6440 0.0350 0.6580 0.1570 ;
    LAYER M0 ;
      RECT 0.5975 0.0400 0.7045 0.0520 ;
      RECT 0.0305 0.1400 0.7465 0.1520 ;
    LAYER V0 ;
      RECT 0.6440 0.0400 0.6580 0.0520 ;
      RECT 0.6440 0.1400 0.6580 0.1520 ;
  END
END gt2_7t_buf_x12_w31_lvt

MACRO gt2_7t_buf_x1_w31_lvt
  CLASS CORE ;
  ORIGIN 0 0 ;
  FOREIGN gt2_6t_buf_x1_w31_lvt 0 0 ;
  SIZE 0.1680 BY 0.1680 ;
  SYMMETRY X Y ;
  SITE gt2_7t ;
  PIN A
    DIRECTION INPUT ;
    USE SIGNAL ;
    PORT
      LAYER M0 ;
        RECT 0.0210 0.1160 0.0535 0.1280 ;
    END
  END A
  PIN Y
    DIRECTION OUTPUT ;
    USE SIGNAL ;
    PORT
      LAYER M1 ;
        RECT 0.1400 0.0110 0.1540 0.1570 ;
      LAYER M0 ;
        RECT 0.1260 0.0160 0.1620 0.0280 ;
        RECT 0.1260 0.1400 0.1620 0.1520 ;
      LAYER V0 ;
        RECT 0.1400 0.0160 0.1540 0.0280 ;
        RECT 0.1400 0.1400 0.1540 0.1520 ;
    END
  END Y
  PIN VDD
    DIRECTION INOUT ;
    USE POWER ;
    SHAPE ABUTMENT ;
    PORT
      LAYER BPR ;
        RECT 0.0000 0.1520 0.1680 0.1840 ;
    END
  END VDD
  PIN VSS
    DIRECTION INOUT ;
    USE GROUND ;
    SHAPE ABUTMENT ;
    PORT
      LAYER BPR ;
        RECT 0.0000 -0.0160 0.1680 0.0160 ;
    END
  END VSS
  OBS
    LAYER M1 ;
      RECT 0.0560 0.0350 0.0700 0.1570 ;
    LAYER M0 ;
      RECT 0.0480 0.0400 0.1375 0.0520 ;
      RECT 0.0480 0.1400 0.0840 0.1520 ;
    LAYER V0 ;
      RECT 0.0560 0.0400 0.0700 0.0520 ;
      RECT 0.0560 0.1400 0.0700 0.1520 ;
  END
END gt2_7t_buf_x1_w31_lvt

MACRO gt2_7t_buf_x2_w31_lvt
  CLASS CORE ;
  ORIGIN 0 0 ;
  FOREIGN gt2_6t_buf_x2_w31_lvt 0 0 ;
  SIZE 0.1680 BY 0.1680 ;
  SYMMETRY X Y ;
  SITE gt2_7t ;
  PIN A
    DIRECTION INPUT ;
    USE SIGNAL ;
    PORT
      LAYER M0 ;
        RECT 0.1145 0.0160 0.1470 0.0280 ;
    END
  END A
  PIN Y
    DIRECTION OUTPUT ;
    USE SIGNAL ;
    PORT
      LAYER M1 ;
        RECT 0.0560 0.0350 0.0700 0.1330 ;
      LAYER M0 ;
        RECT 0.0480 0.0400 0.0840 0.0520 ;
        RECT 0.0420 0.1160 0.0780 0.1280 ;
      LAYER V0 ;
        RECT 0.0560 0.0400 0.0700 0.0520 ;
        RECT 0.0560 0.1160 0.0700 0.1280 ;
    END
  END Y
  PIN VDD
    DIRECTION INOUT ;
    USE POWER ;
    SHAPE ABUTMENT ;
    PORT
      LAYER BPR ;
        RECT 0.0000 0.1520 0.1680 0.1840 ;
    END
  END VDD
  PIN VSS
    DIRECTION INOUT ;
    USE GROUND ;
    SHAPE ABUTMENT ;
    PORT
      LAYER BPR ;
        RECT 0.0000 -0.0160 0.1680 0.0160 ;
    END
  END VSS
  OBS
    LAYER M1 ;
      RECT 0.1400 0.0350 0.1540 0.1570 ;
    LAYER M0 ;
      RECT 0.1260 0.0400 0.1620 0.0520 ;
      RECT 0.0305 0.1400 0.1620 0.1520 ;
    LAYER V0 ;
      RECT 0.1400 0.0400 0.1540 0.0520 ;
      RECT 0.1400 0.1400 0.1540 0.1520 ;
  END
END gt2_7t_buf_x2_w31_lvt

MACRO gt2_7t_buf_x3_w31_lvt
  CLASS CORE ;
  ORIGIN 0 0 ;
  FOREIGN gt2_6t_buf_x3_w31_lvt 0 0 ;
  SIZE 0.2520 BY 0.1680 ;
  SYMMETRY X Y ;
  SITE gt2_7t ;
  PIN A
    DIRECTION INPUT ;
    USE SIGNAL ;
    PORT
      LAYER M0 ;
        RECT 0.0210 0.1160 0.0535 0.1280 ;
    END
  END A
  PIN Y
    DIRECTION OUTPUT ;
    USE SIGNAL ;
    PORT
      LAYER M1 ;
        RECT 0.1400 0.0110 0.1540 0.1330 ;
      LAYER M0 ;
        RECT 0.0935 0.0160 0.2005 0.0280 ;
        RECT 0.1320 0.1160 0.2425 0.1280 ;
      LAYER V0 ;
        RECT 0.1400 0.0160 0.1540 0.0280 ;
        RECT 0.1400 0.1160 0.1540 0.1280 ;
    END
  END Y
  PIN VDD
    DIRECTION INOUT ;
    USE POWER ;
    SHAPE ABUTMENT ;
    PORT
      LAYER BPR ;
        RECT 0.0000 0.1520 0.2520 0.1840 ;
    END
  END VDD
  PIN VSS
    DIRECTION INOUT ;
    USE GROUND ;
    SHAPE ABUTMENT ;
    PORT
      LAYER BPR ;
        RECT 0.0000 -0.0160 0.2520 0.0160 ;
    END
  END VSS
  OBS
    LAYER M1 ;
      RECT 0.0560 0.0110 0.0700 0.1570 ;
    LAYER M0 ;
      RECT 0.0420 0.0160 0.0765 0.0280 ;
      RECT 0.0480 0.1400 0.2215 0.1520 ;
    LAYER V0 ;
      RECT 0.0560 0.0160 0.0700 0.0280 ;
      RECT 0.0560 0.1400 0.0700 0.1520 ;
  END
END gt2_7t_buf_x3_w31_lvt

MACRO gt2_7t_buf_x4_w31_lvt
  CLASS CORE ;
  ORIGIN 0 0 ;
  FOREIGN gt2_6t_buf_x4_w31_lvt 0 0 ;
  SIZE 0.2940 BY 0.1680 ;
  SYMMETRY X Y ;
  SITE gt2_7t ;
  PIN A
    DIRECTION INPUT ;
    USE SIGNAL ;
    PORT
      LAYER M0 ;
        RECT 0.2405 0.0160 0.2730 0.0280 ;
    END
  END A
  PIN Y
    DIRECTION OUTPUT ;
    USE SIGNAL ;
    PORT
      LAYER M1 ;
        RECT 0.1120 0.0350 0.1260 0.1330 ;
      LAYER M0 ;
        RECT 0.0095 0.0400 0.2005 0.0520 ;
        RECT 0.0515 0.1160 0.1585 0.1280 ;
      LAYER V0 ;
        RECT 0.1120 0.0400 0.1260 0.0520 ;
        RECT 0.1120 0.1160 0.1260 0.1280 ;
    END
  END Y
  PIN VDD
    DIRECTION INOUT ;
    USE POWER ;
    SHAPE ABUTMENT ;
    PORT
      LAYER BPR ;
        RECT 0.0000 0.1520 0.2940 0.1840 ;
    END
  END VDD
  PIN VSS
    DIRECTION INOUT ;
    USE GROUND ;
    SHAPE ABUTMENT ;
    PORT
      LAYER BPR ;
        RECT 0.0000 -0.0160 0.2940 0.0160 ;
    END
  END VSS
  OBS
    LAYER M1 ;
      RECT 0.2240 0.0350 0.2380 0.1570 ;
    LAYER M0 ;
      RECT 0.2175 0.0400 0.2520 0.0520 ;
      RECT 0.0305 0.1400 0.2460 0.1520 ;
    LAYER V0 ;
      RECT 0.2240 0.0400 0.2380 0.0520 ;
      RECT 0.2240 0.1400 0.2380 0.1520 ;
  END
END gt2_7t_buf_x4_w31_lvt

MACRO gt2_7t_buf_x6_w31_lvt
  CLASS CORE ;
  ORIGIN 0 0 ;
  FOREIGN gt2_6t_buf_x6_w31_lvt 0 0 ;
  SIZE 0.4200 BY 0.1680 ;
  SYMMETRY X Y ;
  SITE gt2_7t ;
  PIN A
    DIRECTION INPUT ;
    USE SIGNAL ;
    PORT
      LAYER M0 ;
        RECT 0.0305 0.1400 0.0955 0.1520 ;
    END
  END A
  PIN Y
    DIRECTION OUTPUT ;
    USE SIGNAL ;
    PORT
      LAYER M1 ;
        RECT 0.2800 0.0110 0.2940 0.1330 ;
      LAYER M0 ;
        RECT 0.1775 0.0160 0.3685 0.0280 ;
        RECT 0.1355 0.1160 0.4105 0.1280 ;
      LAYER V0 ;
        RECT 0.2800 0.0160 0.2940 0.0280 ;
        RECT 0.2800 0.1160 0.2940 0.1280 ;
    END
  END Y
  PIN VDD
    DIRECTION INOUT ;
    USE POWER ;
    SHAPE ABUTMENT ;
    PORT
      LAYER BPR ;
        RECT 0.0000 0.1520 0.4200 0.1840 ;
    END
  END VDD
  PIN VSS
    DIRECTION INOUT ;
    USE GROUND ;
    SHAPE ABUTMENT ;
    PORT
      LAYER BPR ;
        RECT 0.0000 -0.0160 0.4200 0.0160 ;
    END
  END VSS
  OBS
    LAYER M1 ;
      RECT 0.0560 0.0350 0.0700 0.1330 ;
    LAYER M0 ;
      RECT 0.0480 0.0400 0.3895 0.0520 ;
      RECT 0.0480 0.1160 0.0840 0.1280 ;
    LAYER V0 ;
      RECT 0.0560 0.0400 0.0700 0.0520 ;
      RECT 0.0560 0.1160 0.0700 0.1280 ;
  END
END gt2_7t_buf_x6_w31_lvt

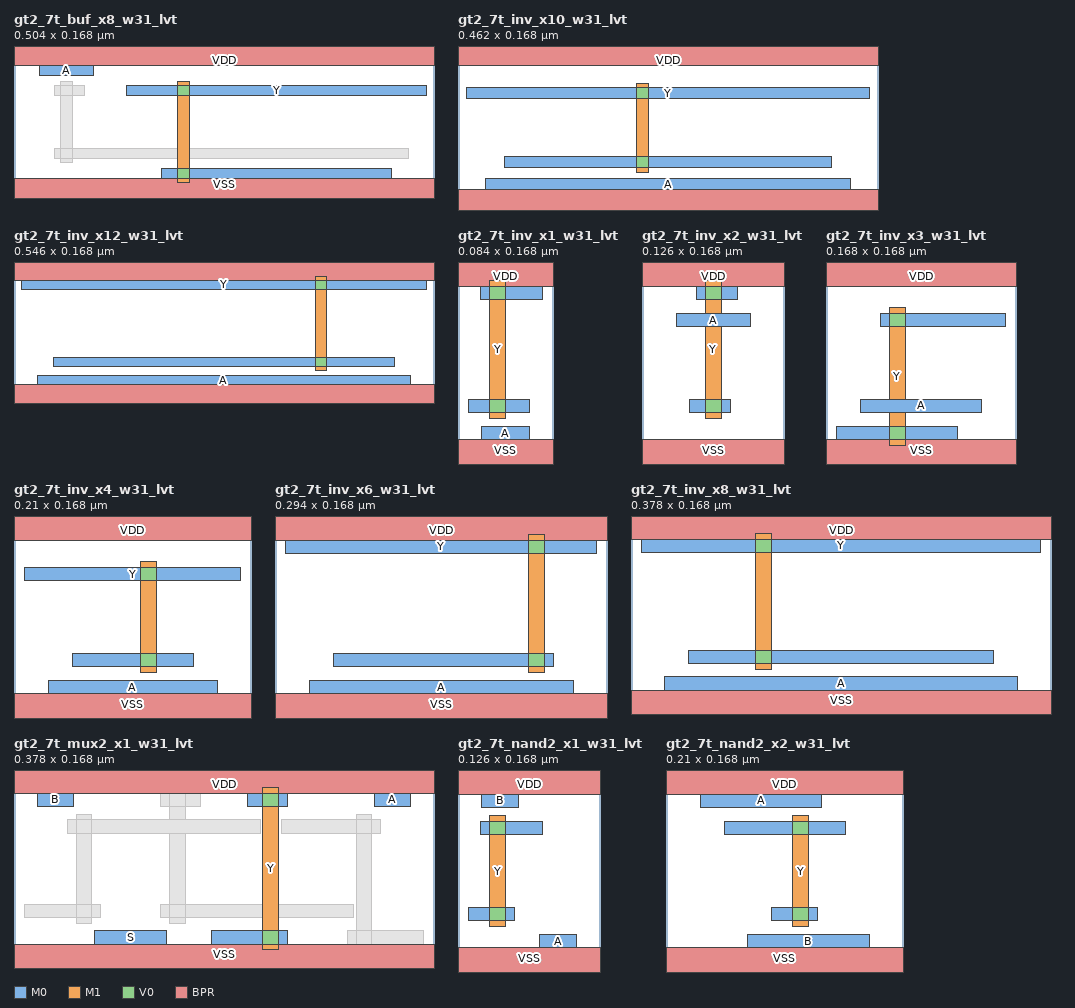
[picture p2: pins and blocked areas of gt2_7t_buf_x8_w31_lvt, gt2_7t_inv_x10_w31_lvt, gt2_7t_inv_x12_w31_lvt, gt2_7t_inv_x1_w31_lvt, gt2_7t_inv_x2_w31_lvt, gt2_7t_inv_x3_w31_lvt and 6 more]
MACRO gt2_7t_buf_x8_w31_lvt
  CLASS CORE ;
  ORIGIN 0 0 ;
  FOREIGN gt2_6t_buf_x8_w31_lvt 0 0 ;
  SIZE 0.5040 BY 0.1680 ;
  SYMMETRY X Y ;
  SITE gt2_7t ;
  PIN A
    DIRECTION INPUT ;
    USE SIGNAL ;
    PORT
      LAYER M0 ;
        RECT 0.0305 0.1400 0.0955 0.1520 ;
    END
  END A
  PIN Y
    DIRECTION OUTPUT ;
    USE SIGNAL ;
    PORT
      LAYER M1 ;
        RECT 0.1960 0.0110 0.2100 0.1330 ;
      LAYER M0 ;
        RECT 0.1775 0.0160 0.4525 0.0280 ;
        RECT 0.1355 0.1160 0.4945 0.1280 ;
      LAYER V0 ;
        RECT 0.1960 0.0160 0.2100 0.0280 ;
        RECT 0.1960 0.1160 0.2100 0.1280 ;
    END
  END Y
  PIN VDD
    DIRECTION INOUT ;
    USE POWER ;
    SHAPE ABUTMENT ;
    PORT
      LAYER BPR ;
        RECT 0.0000 0.1520 0.5040 0.1840 ;
    END
  END VDD
  PIN VSS
    DIRECTION INOUT ;
    USE GROUND ;
    SHAPE ABUTMENT ;
    PORT
      LAYER BPR ;
        RECT 0.0000 -0.0160 0.5040 0.0160 ;
    END
  END VSS
  OBS
    LAYER M1 ;
      RECT 0.0560 0.0350 0.0700 0.1330 ;
    LAYER M0 ;
      RECT 0.0480 0.0400 0.4735 0.0520 ;
      RECT 0.0480 0.1160 0.0840 0.1280 ;
    LAYER V0 ;
      RECT 0.0560 0.0400 0.0700 0.0520 ;
      RECT 0.0560 0.1160 0.0700 0.1280 ;
  END
END gt2_7t_buf_x8_w31_lvt

MACRO gt2_7t_inv_x10_w31_lvt
  CLASS CORE ;
  ORIGIN 0 0 ;
  FOREIGN gt2_6t_inv_x10_w31_lvt 0 0 ;
  SIZE 0.4620 BY 0.1680 ;
  SYMMETRY X Y ;
  SITE gt2_7t ;
  PIN A
    DIRECTION INPUT ;
    USE SIGNAL ;
    PORT
      LAYER M0 ;
        RECT 0.0305 0.0160 0.4315 0.0280 ;
    END
  END A
  PIN Y
    DIRECTION OUTPUT ;
    USE SIGNAL ;
    PORT
      LAYER M1 ;
        RECT 0.1960 0.0350 0.2100 0.1330 ;
      LAYER M0 ;
        RECT 0.0515 0.0400 0.4105 0.0520 ;
        RECT 0.0095 0.1160 0.4525 0.1280 ;
      LAYER V0 ;
        RECT 0.1960 0.0400 0.2100 0.0520 ;
        RECT 0.1960 0.1160 0.2100 0.1280 ;
    END
  END Y
  PIN VDD
    DIRECTION INOUT ;
    USE POWER ;
    SHAPE ABUTMENT ;
    PORT
      LAYER BPR ;
        RECT 0.0000 0.1520 0.4620 0.1840 ;
    END
  END VDD
  PIN VSS
    DIRECTION INOUT ;
    USE GROUND ;
    SHAPE ABUTMENT ;
    PORT
      LAYER BPR ;
        RECT 0.0000 -0.0160 0.4620 0.0160 ;
    END
  END VSS
END gt2_7t_inv_x10_w31_lvt

MACRO gt2_7t_inv_x12_w31_lvt
  CLASS CORE ;
  ORIGIN 0 0 ;
  FOREIGN gt2_6t_inv_x12_w31_lvt 0 0 ;
  SIZE 0.5460 BY 0.1680 ;
  SYMMETRY X Y ;
  SITE gt2_7t ;
  PIN A
    DIRECTION INPUT ;
    USE SIGNAL ;
    PORT
      LAYER M0 ;
        RECT 0.0305 0.0160 0.5155 0.0280 ;
    END
  END A
  PIN Y
    DIRECTION OUTPUT ;
    USE SIGNAL ;
    PORT
      LAYER M1 ;
        RECT 0.3920 0.0350 0.4060 0.1570 ;
      LAYER M0 ;
        RECT 0.0515 0.0400 0.4945 0.0520 ;
        RECT 0.0095 0.1400 0.5365 0.1520 ;
      LAYER V0 ;
        RECT 0.3920 0.0400 0.4060 0.0520 ;
        RECT 0.3920 0.1400 0.4060 0.1520 ;
    END
  END Y
  PIN VDD
    DIRECTION INOUT ;
    USE POWER ;
    SHAPE ABUTMENT ;
    PORT
      LAYER BPR ;
        RECT 0.0000 0.1520 0.5460 0.1840 ;
    END
  END VDD
  PIN VSS
    DIRECTION INOUT ;
    USE GROUND ;
    SHAPE ABUTMENT ;
    PORT
      LAYER BPR ;
        RECT 0.0000 -0.0160 0.5460 0.0160 ;
    END
  END VSS
END gt2_7t_inv_x12_w31_lvt

MACRO gt2_7t_inv_x1_w31_lvt
  CLASS CORE ;
  ORIGIN 0 0 ;
  FOREIGN gt2_6t_inv_x1_w31_lvt 0 0 ;
  SIZE 0.0840 BY 0.1680 ;
  SYMMETRY X Y ;
  SITE gt2_7t ;
  PIN A
    DIRECTION INPUT ;
    USE SIGNAL ;
    PORT
      LAYER M0 ;
        RECT 0.0210 0.0160 0.0630 0.0280 ;
    END
  END A
  PIN Y
    DIRECTION OUTPUT ;
    USE SIGNAL ;
    PORT
      LAYER M1 ;
        RECT 0.0280 0.0350 0.0420 0.1570 ;
      LAYER M0 ;
        RECT 0.0095 0.0400 0.0630 0.0520 ;
        RECT 0.0200 0.1400 0.0745 0.1520 ;
      LAYER V0 ;
        RECT 0.0280 0.0400 0.0420 0.0520 ;
        RECT 0.0280 0.1400 0.0420 0.1520 ;
    END
  END Y
  PIN VDD
    DIRECTION INOUT ;
    USE POWER ;
    SHAPE ABUTMENT ;
    PORT
      LAYER BPR ;
        RECT 0.0000 0.1520 0.0840 0.1840 ;
    END
  END VDD
  PIN VSS
    DIRECTION INOUT ;
    USE GROUND ;
    SHAPE ABUTMENT ;
    PORT
      LAYER BPR ;
        RECT 0.0000 -0.0160 0.0840 0.0160 ;
    END
  END VSS
END gt2_7t_inv_x1_w31_lvt

MACRO gt2_7t_inv_x2_w31_lvt
  CLASS CORE ;
  ORIGIN 0 0 ;
  FOREIGN gt2_6t_inv_x2_w31_lvt 0 0 ;
  SIZE 0.1260 BY 0.1680 ;
  SYMMETRY X Y ;
  SITE gt2_7t ;
  PIN A
    DIRECTION INPUT ;
    USE SIGNAL ;
    PORT
      LAYER M0 ;
        RECT 0.0305 0.1160 0.0955 0.1280 ;
    END
  END A
  PIN Y
    DIRECTION OUTPUT ;
    USE SIGNAL ;
    PORT
      LAYER M1 ;
        RECT 0.0560 0.0350 0.0700 0.1570 ;
      LAYER M0 ;
        RECT 0.0420 0.0400 0.0780 0.0520 ;
        RECT 0.0480 0.1400 0.0840 0.1520 ;
      LAYER V0 ;
        RECT 0.0560 0.0400 0.0700 0.0520 ;
        RECT 0.0560 0.1400 0.0700 0.1520 ;
    END
  END Y
  PIN VDD
    DIRECTION INOUT ;
    USE POWER ;
    SHAPE ABUTMENT ;
    PORT
      LAYER BPR ;
        RECT 0.0000 0.1520 0.1260 0.1840 ;
    END
  END VDD
  PIN VSS
    DIRECTION INOUT ;
    USE GROUND ;
    SHAPE ABUTMENT ;
    PORT
      LAYER BPR ;
        RECT 0.0000 -0.0160 0.1260 0.0160 ;
    END
  END VSS
END gt2_7t_inv_x2_w31_lvt

MACRO gt2_7t_inv_x3_w31_lvt
  CLASS CORE ;
  ORIGIN 0 0 ;
  FOREIGN gt2_6t_inv_x3_w31_lvt 0 0 ;
  SIZE 0.1680 BY 0.1680 ;
  SYMMETRY X Y ;
  SITE gt2_7t ;
  PIN A
    DIRECTION INPUT ;
    USE SIGNAL ;
    PORT
      LAYER M0 ;
        RECT 0.0305 0.0400 0.1375 0.0520 ;
    END
  END A
  PIN Y
    DIRECTION OUTPUT ;
    USE SIGNAL ;
    PORT
      LAYER M1 ;
        RECT 0.0560 0.0110 0.0700 0.1330 ;
      LAYER M0 ;
        RECT 0.0095 0.0160 0.1165 0.0280 ;
        RECT 0.0480 0.1160 0.1585 0.1280 ;
      LAYER V0 ;
        RECT 0.0560 0.0160 0.0700 0.0280 ;
        RECT 0.0560 0.1160 0.0700 0.1280 ;
    END
  END Y
  PIN VDD
    DIRECTION INOUT ;
    USE POWER ;
    SHAPE ABUTMENT ;
    PORT
      LAYER BPR ;
        RECT 0.0000 0.1520 0.1680 0.1840 ;
    END
  END VDD
  PIN VSS
    DIRECTION INOUT ;
    USE GROUND ;
    SHAPE ABUTMENT ;
    PORT
      LAYER BPR ;
        RECT 0.0000 -0.0160 0.1680 0.0160 ;
    END
  END VSS
END gt2_7t_inv_x3_w31_lvt

MACRO gt2_7t_inv_x4_w31_lvt
  CLASS CORE ;
  ORIGIN 0 0 ;
  FOREIGN gt2_6t_inv_x4_w31_lvt 0 0 ;
  SIZE 0.2100 BY 0.1680 ;
  SYMMETRY X Y ;
  SITE gt2_7t ;
  PIN A
    DIRECTION INPUT ;
    USE SIGNAL ;
    PORT
      LAYER M0 ;
        RECT 0.0305 0.0160 0.1795 0.0280 ;
    END
  END A
  PIN Y
    DIRECTION OUTPUT ;
    USE SIGNAL ;
    PORT
      LAYER M1 ;
        RECT 0.1120 0.0350 0.1260 0.1330 ;
      LAYER M0 ;
        RECT 0.0515 0.0400 0.1585 0.0520 ;
        RECT 0.0095 0.1160 0.2005 0.1280 ;
      LAYER V0 ;
        RECT 0.1120 0.0400 0.1260 0.0520 ;
        RECT 0.1120 0.1160 0.1260 0.1280 ;
    END
  END Y
  PIN VDD
    DIRECTION INOUT ;
    USE POWER ;
    SHAPE ABUTMENT ;
    PORT
      LAYER BPR ;
        RECT 0.0000 0.1520 0.2100 0.1840 ;
    END
  END VDD
  PIN VSS
    DIRECTION INOUT ;
    USE GROUND ;
    SHAPE ABUTMENT ;
    PORT
      LAYER BPR ;
        RECT 0.0000 -0.0160 0.2100 0.0160 ;
    END
  END VSS
END gt2_7t_inv_x4_w31_lvt

MACRO gt2_7t_inv_x6_w31_lvt
  CLASS CORE ;
  ORIGIN 0 0 ;
  FOREIGN gt2_6t_inv_x6_w31_lvt 0 0 ;
  SIZE 0.2940 BY 0.1680 ;
  SYMMETRY X Y ;
  SITE gt2_7t ;
  PIN A
    DIRECTION INPUT ;
    USE SIGNAL ;
    PORT
      LAYER M0 ;
        RECT 0.0305 0.0160 0.2635 0.0280 ;
    END
  END A
  PIN Y
    DIRECTION OUTPUT ;
    USE SIGNAL ;
    PORT
      LAYER M1 ;
        RECT 0.2240 0.0350 0.2380 0.1570 ;
      LAYER M0 ;
        RECT 0.0515 0.0400 0.2460 0.0520 ;
        RECT 0.0095 0.1400 0.2845 0.1520 ;
      LAYER V0 ;
        RECT 0.2240 0.0400 0.2380 0.0520 ;
        RECT 0.2240 0.1400 0.2380 0.1520 ;
    END
  END Y
  PIN VDD
    DIRECTION INOUT ;
    USE POWER ;
    SHAPE ABUTMENT ;
    PORT
      LAYER BPR ;
        RECT 0.0000 0.1520 0.2940 0.1840 ;
    END
  END VDD
  PIN VSS
    DIRECTION INOUT ;
    USE GROUND ;
    SHAPE ABUTMENT ;
    PORT
      LAYER BPR ;
        RECT 0.0000 -0.0160 0.2940 0.0160 ;
    END
  END VSS
END gt2_7t_inv_x6_w31_lvt

MACRO gt2_7t_inv_x8_w31_lvt
  CLASS CORE ;
  ORIGIN 0 0 ;
  FOREIGN gt2_6t_inv_x8_w31_lvt 0 0 ;
  SIZE 0.3780 BY 0.1680 ;
  SYMMETRY X Y ;
  SITE gt2_7t ;
  PIN A
    DIRECTION INPUT ;
    USE SIGNAL ;
    PORT
      LAYER M0 ;
        RECT 0.0305 0.0160 0.3475 0.0280 ;
    END
  END A
  PIN Y
    DIRECTION OUTPUT ;
    USE SIGNAL ;
    PORT
      LAYER M1 ;
        RECT 0.1120 0.0350 0.1260 0.1570 ;
      LAYER M0 ;
        RECT 0.0515 0.0400 0.3265 0.0520 ;
        RECT 0.0095 0.1400 0.3685 0.1520 ;
      LAYER V0 ;
        RECT 0.1120 0.0400 0.1260 0.0520 ;
        RECT 0.1120 0.1400 0.1260 0.1520 ;
    END
  END Y
  PIN VDD
    DIRECTION INOUT ;
    USE POWER ;
    SHAPE ABUTMENT ;
    PORT
      LAYER BPR ;
        RECT 0.0000 0.1520 0.3780 0.1840 ;
    END
  END VDD
  PIN VSS
    DIRECTION INOUT ;
    USE GROUND ;
    SHAPE ABUTMENT ;
    PORT
      LAYER BPR ;
        RECT 0.0000 -0.0160 0.3780 0.0160 ;
    END
  END VSS
END gt2_7t_inv_x8_w31_lvt

MACRO gt2_7t_mux2_x1_w31_lvt
  CLASS CORE ;
  ORIGIN 0 0 ;
  FOREIGN gt2_6t_mux2_x1_w31_lvt 0 0 ;
  SIZE 0.3780 BY 0.1680 ;
  SYMMETRY X Y ;
  SITE gt2_7t ;
  PIN A
    DIRECTION INPUT ;
    USE SIGNAL ;
    PORT
      LAYER M0 ;
        RECT 0.3245 0.1400 0.3570 0.1520 ;
    END
  END A
  PIN B
    DIRECTION INPUT ;
    USE SIGNAL ;
    PORT
      LAYER M0 ;
        RECT 0.0210 0.1400 0.0535 0.1520 ;
    END
  END B
  PIN S
    DIRECTION INPUT ;
    USE SIGNAL ;
    PORT
      LAYER M0 ;
        RECT 0.0725 0.0160 0.1375 0.0280 ;
    END
  END S
  PIN Y
    DIRECTION OUTPUT ;
    USE SIGNAL ;
    PORT
      LAYER M1 ;
        RECT 0.2240 0.0110 0.2380 0.1570 ;
      LAYER M0 ;
        RECT 0.1775 0.0160 0.2460 0.0280 ;
        RECT 0.2100 0.1400 0.2460 0.1520 ;
      LAYER V0 ;
        RECT 0.2240 0.0160 0.2380 0.0280 ;
        RECT 0.2240 0.1400 0.2380 0.1520 ;
    END
  END Y
  PIN VDD
    DIRECTION INOUT ;
    USE POWER ;
    SHAPE ABUTMENT ;
    PORT
      LAYER BPR ;
        RECT 0.0000 0.1520 0.3780 0.1840 ;
    END
  END VDD
  PIN VSS
    DIRECTION INOUT ;
    USE GROUND ;
    SHAPE ABUTMENT ;
    PORT
      LAYER BPR ;
        RECT 0.0000 -0.0160 0.3780 0.0160 ;
    END
  END VSS
  OBS
    LAYER M1 ;
      RECT 0.3080 0.0110 0.3220 0.1330 ;
      RECT 0.0560 0.0350 0.0700 0.1330 ;
      RECT 0.1400 0.0350 0.1540 0.1570 ;
    LAYER M0 ;
      RECT 0.3000 0.0160 0.3685 0.0280 ;
      RECT 0.2405 0.1160 0.3300 0.1280 ;
      RECT 0.0095 0.0400 0.0780 0.0520 ;
      RECT 0.0480 0.1160 0.2215 0.1280 ;
      RECT 0.1320 0.0400 0.3055 0.0520 ;
      RECT 0.1320 0.1400 0.1680 0.1520 ;
    LAYER V0 ;
      RECT 0.3080 0.0160 0.3220 0.0280 ;
      RECT 0.3080 0.1160 0.3220 0.1280 ;
      RECT 0.0560 0.0400 0.0700 0.0520 ;
      RECT 0.0560 0.1160 0.0700 0.1280 ;
      RECT 0.1400 0.0400 0.1540 0.0520 ;
      RECT 0.1400 0.1400 0.1540 0.1520 ;
  END
END gt2_7t_mux2_x1_w31_lvt

MACRO gt2_7t_nand2_x1_w31_lvt
  CLASS CORE ;
  ORIGIN 0 0 ;
  FOREIGN gt2_6t_nand2_x1_w31_lvt 0 0 ;
  SIZE 0.1260 BY 0.1680 ;
  SYMMETRY X Y ;
  SITE gt2_7t ;
  PIN A
    DIRECTION INPUT ;
    USE SIGNAL ;
    PORT
      LAYER M0 ;
        RECT 0.0725 0.0160 0.1050 0.0280 ;
    END
  END A
  PIN B
    DIRECTION INPUT ;
    USE SIGNAL ;
    PORT
      LAYER M0 ;
        RECT 0.0210 0.1400 0.0535 0.1520 ;
    END
  END B
  PIN Y
    DIRECTION OUTPUT ;
    USE SIGNAL ;
    PORT
      LAYER M1 ;
        RECT 0.0280 0.0350 0.0420 0.1330 ;
      LAYER M0 ;
        RECT 0.0095 0.0400 0.0500 0.0520 ;
        RECT 0.0200 0.1160 0.0745 0.1280 ;
      LAYER V0 ;
        RECT 0.0280 0.0400 0.0420 0.0520 ;
        RECT 0.0280 0.1160 0.0420 0.1280 ;
    END
  END Y
  PIN VDD
    DIRECTION INOUT ;
    USE POWER ;
    SHAPE ABUTMENT ;
    PORT
      LAYER BPR ;
        RECT 0.0000 0.1520 0.1260 0.1840 ;
    END
  END VDD
  PIN VSS
    DIRECTION INOUT ;
    USE GROUND ;
    SHAPE ABUTMENT ;
    PORT
      LAYER BPR ;
        RECT 0.0000 -0.0160 0.1260 0.0160 ;
    END
  END VSS
END gt2_7t_nand2_x1_w31_lvt

MACRO gt2_7t_nand2_x2_w31_lvt
  CLASS CORE ;
  ORIGIN 0 0 ;
  FOREIGN gt2_6t_nand2_x2_w31_lvt 0 0 ;
  SIZE 0.2100 BY 0.1680 ;
  SYMMETRY X Y ;
  SITE gt2_7t ;
  PIN A
    DIRECTION INPUT ;
    USE SIGNAL ;
    PORT
      LAYER M0 ;
        RECT 0.0305 0.1400 0.1375 0.1520 ;
    END
  END A
  PIN B
    DIRECTION INPUT ;
    USE SIGNAL ;
    PORT
      LAYER M0 ;
        RECT 0.0725 0.0160 0.1795 0.0280 ;
    END
  END B
  PIN Y
    DIRECTION OUTPUT ;
    USE SIGNAL ;
    PORT
      LAYER M1 ;
        RECT 0.1120 0.0350 0.1260 0.1330 ;
      LAYER M0 ;
        RECT 0.0935 0.0400 0.1340 0.0520 ;
        RECT 0.0515 0.1160 0.1585 0.1280 ;
      LAYER V0 ;
        RECT 0.1120 0.0400 0.1260 0.0520 ;
        RECT 0.1120 0.1160 0.1260 0.1280 ;
    END
  END Y
  PIN VDD
    DIRECTION INOUT ;
    USE POWER ;
    SHAPE ABUTMENT ;
    PORT
      LAYER BPR ;
        RECT 0.0000 0.1520 0.2100 0.1840 ;
    END
  END VDD
  PIN VSS
    DIRECTION INOUT ;
    USE GROUND ;
    SHAPE ABUTMENT ;
    PORT
      LAYER BPR ;
        RECT 0.0000 -0.0160 0.2100 0.0160 ;
    END
  END VSS
END gt2_7t_nand2_x2_w31_lvt

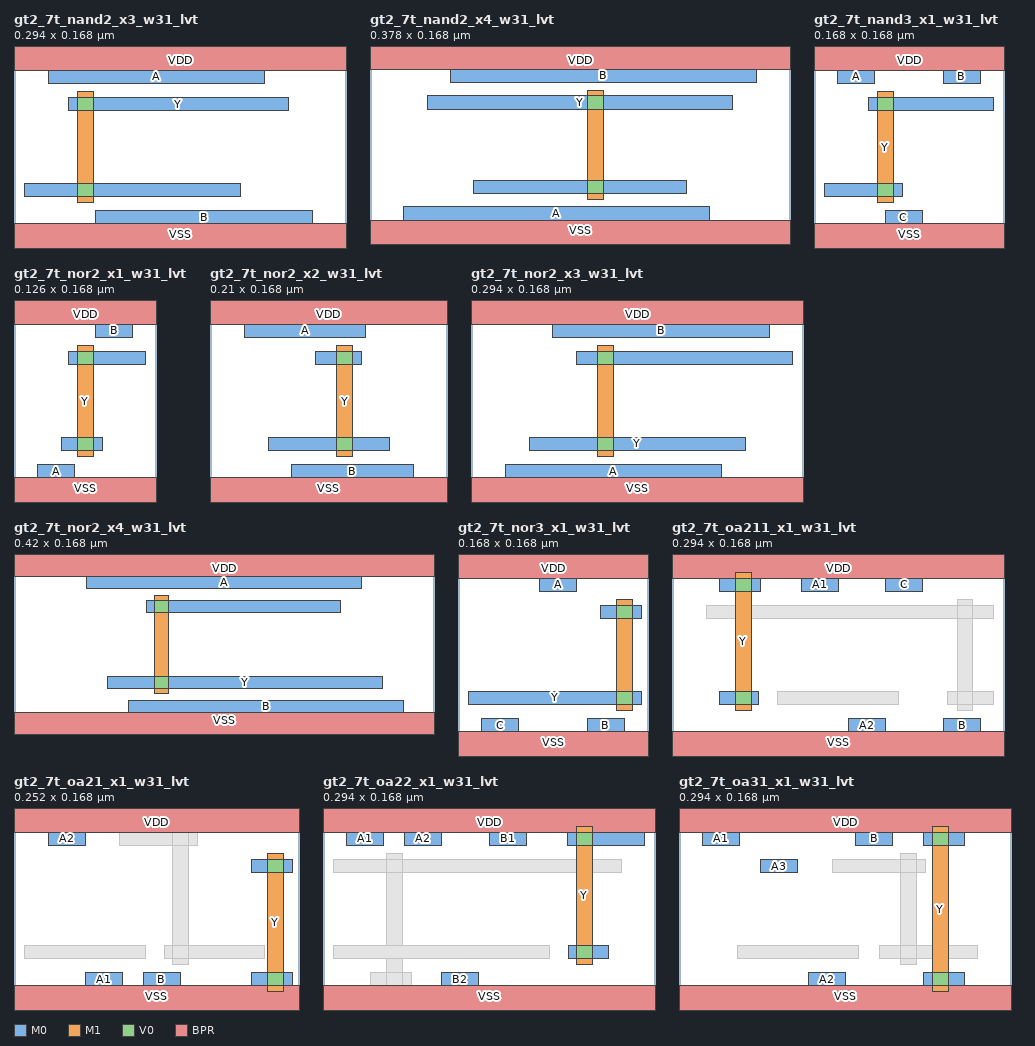
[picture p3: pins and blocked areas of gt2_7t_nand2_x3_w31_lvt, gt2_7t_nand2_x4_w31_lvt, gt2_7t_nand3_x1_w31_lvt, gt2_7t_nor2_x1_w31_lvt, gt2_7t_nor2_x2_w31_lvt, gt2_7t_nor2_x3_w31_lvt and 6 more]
MACRO gt2_7t_nand2_x3_w31_lvt
  CLASS CORE ;
  ORIGIN 0 0 ;
  FOREIGN gt2_6t_nand2_x3_w31_lvt 0 0 ;
  SIZE 0.2940 BY 0.1680 ;
  SYMMETRY X Y ;
  SITE gt2_7t ;
  PIN A
    DIRECTION INPUT ;
    USE SIGNAL ;
    PORT
      LAYER M0 ;
        RECT 0.0305 0.1400 0.2215 0.1520 ;
    END
  END A
  PIN B
    DIRECTION INPUT ;
    USE SIGNAL ;
    PORT
      LAYER M0 ;
        RECT 0.0725 0.0160 0.2635 0.0280 ;
    END
  END B
  PIN Y
    DIRECTION OUTPUT ;
    USE SIGNAL ;
    PORT
      LAYER M1 ;
        RECT 0.0560 0.0350 0.0700 0.1330 ;
      LAYER M0 ;
        RECT 0.0095 0.0400 0.2005 0.0520 ;
        RECT 0.0480 0.1160 0.2425 0.1280 ;
      LAYER V0 ;
        RECT 0.0560 0.0400 0.0700 0.0520 ;
        RECT 0.0560 0.1160 0.0700 0.1280 ;
    END
  END Y
  PIN VDD
    DIRECTION INOUT ;
    USE POWER ;
    SHAPE ABUTMENT ;
    PORT
      LAYER BPR ;
        RECT 0.0000 0.1520 0.2940 0.1840 ;
    END
  END VDD
  PIN VSS
    DIRECTION INOUT ;
    USE GROUND ;
    SHAPE ABUTMENT ;
    PORT
      LAYER BPR ;
        RECT 0.0000 -0.0160 0.2940 0.0160 ;
    END
  END VSS
END gt2_7t_nand2_x3_w31_lvt

MACRO gt2_7t_nand2_x4_w31_lvt
  CLASS CORE ;
  ORIGIN 0 0 ;
  FOREIGN gt2_6t_nand2_x4_w31_lvt 0 0 ;
  SIZE 0.3780 BY 0.1680 ;
  SYMMETRY X Y ;
  SITE gt2_7t ;
  PIN A
    DIRECTION INPUT ;
    USE SIGNAL ;
    PORT
      LAYER M0 ;
        RECT 0.0305 0.0160 0.3055 0.0280 ;
    END
  END A
  PIN B
    DIRECTION INPUT ;
    USE SIGNAL ;
    PORT
      LAYER M0 ;
        RECT 0.0725 0.1400 0.3475 0.1520 ;
    END
  END B
  PIN Y
    DIRECTION OUTPUT ;
    USE SIGNAL ;
    PORT
      LAYER M1 ;
        RECT 0.1960 0.0350 0.2100 0.1330 ;
      LAYER M0 ;
        RECT 0.0935 0.0400 0.2845 0.0520 ;
        RECT 0.0515 0.1160 0.3265 0.1280 ;
      LAYER V0 ;
        RECT 0.1960 0.0400 0.2100 0.0520 ;
        RECT 0.1960 0.1160 0.2100 0.1280 ;
    END
  END Y
  PIN VDD
    DIRECTION INOUT ;
    USE POWER ;
    SHAPE ABUTMENT ;
    PORT
      LAYER BPR ;
        RECT 0.0000 0.1520 0.3780 0.1840 ;
    END
  END VDD
  PIN VSS
    DIRECTION INOUT ;
    USE GROUND ;
    SHAPE ABUTMENT ;
    PORT
      LAYER BPR ;
        RECT 0.0000 -0.0160 0.3780 0.0160 ;
    END
  END VSS
END gt2_7t_nand2_x4_w31_lvt

MACRO gt2_7t_nand3_x1_w31_lvt
  CLASS CORE ;
  ORIGIN 0 0 ;
  FOREIGN gt2_6t_nand3_x1_w31_lvt 0 0 ;
  SIZE 0.1680 BY 0.1680 ;
  SYMMETRY X Y ;
  SITE gt2_7t ;
  PIN A
    DIRECTION INPUT ;
    USE SIGNAL ;
    PORT
      LAYER M0 ;
        RECT 0.0210 0.1400 0.0535 0.1520 ;
    END
  END A
  PIN B
    DIRECTION INPUT ;
    USE SIGNAL ;
    PORT
      LAYER M0 ;
        RECT 0.1145 0.1400 0.1470 0.1520 ;
    END
  END B
  PIN C
    DIRECTION INPUT ;
    USE SIGNAL ;
    PORT
      LAYER M0 ;
        RECT 0.0630 0.0160 0.0955 0.0280 ;
    END
  END C
  PIN Y
    DIRECTION OUTPUT ;
    USE SIGNAL ;
    PORT
      LAYER M1 ;
        RECT 0.0560 0.0350 0.0700 0.1330 ;
      LAYER M0 ;
        RECT 0.0095 0.0400 0.0780 0.0520 ;
        RECT 0.0480 0.1160 0.1585 0.1280 ;
      LAYER V0 ;
        RECT 0.0560 0.0400 0.0700 0.0520 ;
        RECT 0.0560 0.1160 0.0700 0.1280 ;
    END
  END Y
  PIN VDD
    DIRECTION INOUT ;
    USE POWER ;
    SHAPE ABUTMENT ;
    PORT
      LAYER BPR ;
        RECT 0.0000 0.1520 0.1680 0.1840 ;
    END
  END VDD
  PIN VSS
    DIRECTION INOUT ;
    USE GROUND ;
    SHAPE ABUTMENT ;
    PORT
      LAYER BPR ;
        RECT 0.0000 -0.0160 0.1680 0.0160 ;
    END
  END VSS
END gt2_7t_nand3_x1_w31_lvt

MACRO gt2_7t_nor2_x1_w31_lvt
  CLASS CORE ;
  ORIGIN 0 0 ;
  FOREIGN gt2_6t_nor2_x1_w31_lvt 0 0 ;
  SIZE 0.1260 BY 0.1680 ;
  SYMMETRY X Y ;
  SITE gt2_7t ;
  PIN A
    DIRECTION INPUT ;
    USE SIGNAL ;
    PORT
      LAYER M0 ;
        RECT 0.0210 0.0160 0.0535 0.0280 ;
    END
  END A
  PIN B
    DIRECTION INPUT ;
    USE SIGNAL ;
    PORT
      LAYER M0 ;
        RECT 0.0725 0.1400 0.1050 0.1520 ;
    END
  END B
  PIN Y
    DIRECTION OUTPUT ;
    USE SIGNAL ;
    PORT
      LAYER M1 ;
        RECT 0.0560 0.0350 0.0700 0.1330 ;
      LAYER M0 ;
        RECT 0.0420 0.0400 0.0780 0.0520 ;
        RECT 0.0480 0.1160 0.1165 0.1280 ;
      LAYER V0 ;
        RECT 0.0560 0.0400 0.0700 0.0520 ;
        RECT 0.0560 0.1160 0.0700 0.1280 ;
    END
  END Y
  PIN VDD
    DIRECTION INOUT ;
    USE POWER ;
    SHAPE ABUTMENT ;
    PORT
      LAYER BPR ;
        RECT 0.0000 0.1520 0.1260 0.1840 ;
    END
  END VDD
  PIN VSS
    DIRECTION INOUT ;
    USE GROUND ;
    SHAPE ABUTMENT ;
    PORT
      LAYER BPR ;
        RECT 0.0000 -0.0160 0.1260 0.0160 ;
    END
  END VSS
END gt2_7t_nor2_x1_w31_lvt

MACRO gt2_7t_nor2_x2_w31_lvt
  CLASS CORE ;
  ORIGIN 0 0 ;
  FOREIGN gt2_6t_nor2_x2_w31_lvt 0 0 ;
  SIZE 0.2100 BY 0.1680 ;
  SYMMETRY X Y ;
  SITE gt2_7t ;
  PIN A
    DIRECTION INPUT ;
    USE SIGNAL ;
    PORT
      LAYER M0 ;
        RECT 0.0305 0.1400 0.1375 0.1520 ;
    END
  END A
  PIN B
    DIRECTION INPUT ;
    USE SIGNAL ;
    PORT
      LAYER M0 ;
        RECT 0.0725 0.0160 0.1795 0.0280 ;
    END
  END B
  PIN Y
    DIRECTION OUTPUT ;
    USE SIGNAL ;
    PORT
      LAYER M1 ;
        RECT 0.1120 0.0350 0.1260 0.1330 ;
      LAYER M0 ;
        RECT 0.0515 0.0400 0.1585 0.0520 ;
        RECT 0.0935 0.1160 0.1340 0.1280 ;
      LAYER V0 ;
        RECT 0.1120 0.0400 0.1260 0.0520 ;
        RECT 0.1120 0.1160 0.1260 0.1280 ;
    END
  END Y
  PIN VDD
    DIRECTION INOUT ;
    USE POWER ;
    SHAPE ABUTMENT ;
    PORT
      LAYER BPR ;
        RECT 0.0000 0.1520 0.2100 0.1840 ;
    END
  END VDD
  PIN VSS
    DIRECTION INOUT ;
    USE GROUND ;
    SHAPE ABUTMENT ;
    PORT
      LAYER BPR ;
        RECT 0.0000 -0.0160 0.2100 0.0160 ;
    END
  END VSS
END gt2_7t_nor2_x2_w31_lvt

MACRO gt2_7t_nor2_x3_w31_lvt
  CLASS CORE ;
  ORIGIN 0 0 ;
  FOREIGN gt2_6t_nor2_x3_w31_lvt 0 0 ;
  SIZE 0.2940 BY 0.1680 ;
  SYMMETRY X Y ;
  SITE gt2_7t ;
  PIN A
    DIRECTION INPUT ;
    USE SIGNAL ;
    PORT
      LAYER M0 ;
        RECT 0.0305 0.0160 0.2215 0.0280 ;
    END
  END A
  PIN B
    DIRECTION INPUT ;
    USE SIGNAL ;
    PORT
      LAYER M0 ;
        RECT 0.0725 0.1400 0.2635 0.1520 ;
    END
  END B
  PIN Y
    DIRECTION OUTPUT ;
    USE SIGNAL ;
    PORT
      LAYER M1 ;
        RECT 0.1120 0.0350 0.1260 0.1330 ;
      LAYER M0 ;
        RECT 0.0515 0.0400 0.2425 0.0520 ;
        RECT 0.0935 0.1160 0.2845 0.1280 ;
      LAYER V0 ;
        RECT 0.1120 0.0400 0.1260 0.0520 ;
        RECT 0.1120 0.1160 0.1260 0.1280 ;
    END
  END Y
  PIN VDD
    DIRECTION INOUT ;
    USE POWER ;
    SHAPE ABUTMENT ;
    PORT
      LAYER BPR ;
        RECT 0.0000 0.1520 0.2940 0.1840 ;
    END
  END VDD
  PIN VSS
    DIRECTION INOUT ;
    USE GROUND ;
    SHAPE ABUTMENT ;
    PORT
      LAYER BPR ;
        RECT 0.0000 -0.0160 0.2940 0.0160 ;
    END
  END VSS
END gt2_7t_nor2_x3_w31_lvt

MACRO gt2_7t_nor2_x4_w31_lvt
  CLASS CORE ;
  ORIGIN 0 0 ;
  FOREIGN gt2_6t_nor2_x4_w31_lvt 0 0 ;
  SIZE 0.4200 BY 0.1680 ;
  SYMMETRY X Y ;
  SITE gt2_7t ;
  PIN A
    DIRECTION INPUT ;
    USE SIGNAL ;
    PORT
      LAYER M0 ;
        RECT 0.0725 0.1400 0.3475 0.1520 ;
    END
  END A
  PIN B
    DIRECTION INPUT ;
    USE SIGNAL ;
    PORT
      LAYER M0 ;
        RECT 0.1145 0.0160 0.3895 0.0280 ;
    END
  END B
  PIN Y
    DIRECTION OUTPUT ;
    USE SIGNAL ;
    PORT
      LAYER M1 ;
        RECT 0.1400 0.0350 0.1540 0.1330 ;
      LAYER M0 ;
        RECT 0.0935 0.0400 0.3685 0.0520 ;
        RECT 0.1320 0.1160 0.3265 0.1280 ;
      LAYER V0 ;
        RECT 0.1400 0.0400 0.1540 0.0520 ;
        RECT 0.1400 0.1160 0.1540 0.1280 ;
    END
  END Y
  PIN VDD
    DIRECTION INOUT ;
    USE POWER ;
    SHAPE ABUTMENT ;
    PORT
      LAYER BPR ;
        RECT 0.0000 0.1520 0.4200 0.1840 ;
    END
  END VDD
  PIN VSS
    DIRECTION INOUT ;
    USE GROUND ;
    SHAPE ABUTMENT ;
    PORT
      LAYER BPR ;
        RECT 0.0000 -0.0160 0.4200 0.0160 ;
    END
  END VSS
END gt2_7t_nor2_x4_w31_lvt

MACRO gt2_7t_nor3_x1_w31_lvt
  CLASS CORE ;
  ORIGIN 0 0 ;
  FOREIGN gt2_6t_nor3_x1_w31_lvt 0 0 ;
  SIZE 0.1680 BY 0.1680 ;
  SYMMETRY X Y ;
  SITE gt2_7t ;
  PIN A
    DIRECTION INPUT ;
    USE SIGNAL ;
    PORT
      LAYER M0 ;
        RECT 0.0725 0.1400 0.1050 0.1520 ;
    END
  END A
  PIN B
    DIRECTION INPUT ;
    USE SIGNAL ;
    PORT
      LAYER M0 ;
        RECT 0.1145 0.0160 0.1470 0.0280 ;
    END
  END B
  PIN C
    DIRECTION INPUT ;
    USE SIGNAL ;
    PORT
      LAYER M0 ;
        RECT 0.0210 0.0160 0.0535 0.0280 ;
    END
  END C
  PIN Y
    DIRECTION OUTPUT ;
    USE SIGNAL ;
    PORT
      LAYER M1 ;
        RECT 0.1400 0.0350 0.1540 0.1330 ;
      LAYER M0 ;
        RECT 0.0095 0.0400 0.1620 0.0520 ;
        RECT 0.1260 0.1160 0.1620 0.1280 ;
      LAYER V0 ;
        RECT 0.1400 0.0400 0.1540 0.0520 ;
        RECT 0.1400 0.1160 0.1540 0.1280 ;
    END
  END Y
  PIN VDD
    DIRECTION INOUT ;
    USE POWER ;
    SHAPE ABUTMENT ;
    PORT
      LAYER BPR ;
        RECT 0.0000 0.1520 0.1680 0.1840 ;
    END
  END VDD
  PIN VSS
    DIRECTION INOUT ;
    USE GROUND ;
    SHAPE ABUTMENT ;
    PORT
      LAYER BPR ;
        RECT 0.0000 -0.0160 0.1680 0.0160 ;
    END
  END VSS
END gt2_7t_nor3_x1_w31_lvt

MACRO gt2_7t_oa211_x1_w31_lvt
  CLASS CORE ;
  ORIGIN 0 0 ;
  FOREIGN gt2_6t_oa211_x1_w31_lvt 0 0 ;
  SIZE 0.2940 BY 0.1680 ;
  SYMMETRY X Y ;
  SITE gt2_7t ;
  PIN A1
    DIRECTION INPUT ;
    USE SIGNAL ;
    PORT
      LAYER M0 ;
        RECT 0.1145 0.1400 0.1470 0.1520 ;
    END
  END A1
  PIN A2
    DIRECTION INPUT ;
    USE SIGNAL ;
    PORT
      LAYER M0 ;
        RECT 0.1565 0.0160 0.1890 0.0280 ;
    END
  END A2
  PIN B
    DIRECTION INPUT ;
    USE SIGNAL ;
    PORT
      LAYER M0 ;
        RECT 0.2405 0.0160 0.2730 0.0280 ;
    END
  END B
  PIN C
    DIRECTION INPUT ;
    USE SIGNAL ;
    PORT
      LAYER M0 ;
        RECT 0.1890 0.1400 0.2215 0.1520 ;
    END
  END C
  PIN Y
    DIRECTION OUTPUT ;
    USE SIGNAL ;
    PORT
      LAYER M1 ;
        RECT 0.0560 0.0350 0.0700 0.1570 ;
      LAYER M0 ;
        RECT 0.0420 0.0400 0.0765 0.0520 ;
        RECT 0.0420 0.1400 0.0780 0.1520 ;
      LAYER V0 ;
        RECT 0.0560 0.0400 0.0700 0.0520 ;
        RECT 0.0560 0.1400 0.0700 0.1520 ;
    END
  END Y
  PIN VDD
    DIRECTION INOUT ;
    USE POWER ;
    SHAPE ABUTMENT ;
    PORT
      LAYER BPR ;
        RECT 0.0000 0.1520 0.2940 0.1840 ;
    END
  END VDD
  PIN VSS
    DIRECTION INOUT ;
    USE GROUND ;
    SHAPE ABUTMENT ;
    PORT
      LAYER BPR ;
        RECT 0.0000 -0.0160 0.2940 0.0160 ;
    END
  END VSS
  OBS
    LAYER M1 ;
      RECT 0.2520 0.0350 0.2660 0.1330 ;
    LAYER M0 ;
      RECT 0.0935 0.0400 0.2005 0.0520 ;
      RECT 0.2440 0.0400 0.2845 0.0520 ;
      RECT 0.0305 0.1160 0.2845 0.1280 ;
    LAYER V0 ;
      RECT 0.2520 0.0400 0.2660 0.0520 ;
      RECT 0.2520 0.1160 0.2660 0.1280 ;
  END
END gt2_7t_oa211_x1_w31_lvt

MACRO gt2_7t_oa21_x1_w31_lvt
  CLASS CORE ;
  ORIGIN 0 0 ;
  FOREIGN gt2_6t_oa21_x1_w31_lvt 0 0 ;
  SIZE 0.2520 BY 0.1680 ;
  SYMMETRY X Y ;
  SITE gt2_7t ;
  PIN A1
    DIRECTION INPUT ;
    USE SIGNAL ;
    PORT
      LAYER M0 ;
        RECT 0.0630 0.0160 0.0955 0.0280 ;
    END
  END A1
  PIN A2
    DIRECTION INPUT ;
    USE SIGNAL ;
    PORT
      LAYER M0 ;
        RECT 0.0305 0.1400 0.0630 0.1520 ;
    END
  END A2
  PIN B
    DIRECTION INPUT ;
    USE SIGNAL ;
    PORT
      LAYER M0 ;
        RECT 0.1145 0.0160 0.1470 0.0280 ;
    END
  END B
  PIN Y
    DIRECTION OUTPUT ;
    USE SIGNAL ;
    PORT
      LAYER M1 ;
        RECT 0.2240 0.0110 0.2380 0.1330 ;
      LAYER M0 ;
        RECT 0.2100 0.0160 0.2460 0.0280 ;
        RECT 0.2100 0.1160 0.2460 0.1280 ;
      LAYER V0 ;
        RECT 0.2240 0.0160 0.2380 0.0280 ;
        RECT 0.2240 0.1160 0.2380 0.1280 ;
    END
  END Y
  PIN VDD
    DIRECTION INOUT ;
    USE POWER ;
    SHAPE ABUTMENT ;
    PORT
      LAYER BPR ;
        RECT 0.0000 0.1520 0.2520 0.1840 ;
    END
  END VDD
  PIN VSS
    DIRECTION INOUT ;
    USE GROUND ;
    SHAPE ABUTMENT ;
    PORT
      LAYER BPR ;
        RECT 0.0000 -0.0160 0.2520 0.0160 ;
    END
  END VSS
  OBS
    LAYER M1 ;
      RECT 0.1400 0.0350 0.1540 0.1570 ;
    LAYER M0 ;
      RECT 0.0095 0.0400 0.1165 0.0520 ;
      RECT 0.1335 0.0400 0.2215 0.0520 ;
      RECT 0.0935 0.1400 0.1620 0.1520 ;
    LAYER V0 ;
      RECT 0.1400 0.0400 0.1540 0.0520 ;
      RECT 0.1400 0.1400 0.1540 0.1520 ;
  END
END gt2_7t_oa21_x1_w31_lvt

MACRO gt2_7t_oa22_x1_w31_lvt
  CLASS CORE ;
  ORIGIN 0 0 ;
  FOREIGN gt2_6t_oa22_x1_w31_lvt 0 0 ;
  SIZE 0.2940 BY 0.1680 ;
  SYMMETRY X Y ;
  SITE gt2_7t ;
  PIN A1
    DIRECTION INPUT ;
    USE SIGNAL ;
    PORT
      LAYER M0 ;
        RECT 0.0210 0.1400 0.0535 0.1520 ;
    END
  END A1
  PIN A2
    DIRECTION INPUT ;
    USE SIGNAL ;
    PORT
      LAYER M0 ;
        RECT 0.0725 0.1400 0.1050 0.1520 ;
    END
  END A2
  PIN B1
    DIRECTION INPUT ;
    USE SIGNAL ;
    PORT
      LAYER M0 ;
        RECT 0.1470 0.1400 0.1795 0.1520 ;
    END
  END B1
  PIN B2
    DIRECTION INPUT ;
    USE SIGNAL ;
    PORT
      LAYER M0 ;
        RECT 0.1050 0.0160 0.1375 0.0280 ;
    END
  END B2
  PIN Y
    DIRECTION OUTPUT ;
    USE SIGNAL ;
    PORT
      LAYER M1 ;
        RECT 0.2240 0.0350 0.2380 0.1570 ;
      LAYER M0 ;
        RECT 0.2175 0.0400 0.2520 0.0520 ;
        RECT 0.2160 0.1400 0.2845 0.1520 ;
      LAYER V0 ;
        RECT 0.2240 0.0400 0.2380 0.0520 ;
        RECT 0.2240 0.1400 0.2380 0.1520 ;
    END
  END Y
  PIN VDD
    DIRECTION INOUT ;
    USE POWER ;
    SHAPE ABUTMENT ;
    PORT
      LAYER BPR ;
        RECT 0.0000 0.1520 0.2940 0.1840 ;
    END
  END VDD
  PIN VSS
    DIRECTION INOUT ;
    USE GROUND ;
    SHAPE ABUTMENT ;
    PORT
      LAYER BPR ;
        RECT 0.0000 -0.0160 0.2940 0.0160 ;
    END
  END VSS
  OBS
    LAYER M1 ;
      RECT 0.0560 0.0110 0.0700 0.1330 ;
    LAYER M0 ;
      RECT 0.0095 0.0400 0.2005 0.0520 ;
      RECT 0.0420 0.0160 0.0780 0.0280 ;
      RECT 0.0095 0.1160 0.2635 0.1280 ;
    LAYER V0 ;
      RECT 0.0560 0.0160 0.0700 0.0280 ;
      RECT 0.0560 0.1160 0.0700 0.1280 ;
  END
END gt2_7t_oa22_x1_w31_lvt

MACRO gt2_7t_oa31_x1_w31_lvt
  CLASS CORE ;
  ORIGIN 0 0 ;
  FOREIGN gt2_6t_oa31_x1_w31_lvt 0 0 ;
  SIZE 0.2940 BY 0.1680 ;
  SYMMETRY X Y ;
  SITE gt2_7t ;
  PIN A1
    DIRECTION INPUT ;
    USE SIGNAL ;
    PORT
      LAYER M0 ;
        RECT 0.0210 0.1400 0.0535 0.1520 ;
    END
  END A1
  PIN A2
    DIRECTION INPUT ;
    USE SIGNAL ;
    PORT
      LAYER M0 ;
        RECT 0.1145 0.0160 0.1470 0.0280 ;
    END
  END A2
  PIN A3
    DIRECTION INPUT ;
    USE SIGNAL ;
    PORT
      LAYER M0 ;
        RECT 0.0725 0.1160 0.1050 0.1280 ;
    END
  END A3
  PIN B
    DIRECTION INPUT ;
    USE SIGNAL ;
    PORT
      LAYER M0 ;
        RECT 0.1565 0.1400 0.1890 0.1520 ;
    END
  END B
  PIN Y
    DIRECTION OUTPUT ;
    USE SIGNAL ;
    PORT
      LAYER M1 ;
        RECT 0.2240 0.0110 0.2380 0.1570 ;
      LAYER M0 ;
        RECT 0.2160 0.0160 0.2520 0.0280 ;
        RECT 0.2160 0.1400 0.2520 0.1520 ;
      LAYER V0 ;
        RECT 0.2240 0.0160 0.2380 0.0280 ;
        RECT 0.2240 0.1400 0.2380 0.1520 ;
    END
  END Y
  PIN VDD
    DIRECTION INOUT ;
    USE POWER ;
    SHAPE ABUTMENT ;
    PORT
      LAYER BPR ;
        RECT 0.0000 0.1520 0.2940 0.1840 ;
    END
  END VDD
  PIN VSS
    DIRECTION INOUT ;
    USE GROUND ;
    SHAPE ABUTMENT ;
    PORT
      LAYER BPR ;
        RECT 0.0000 -0.0160 0.2940 0.0160 ;
    END
  END VSS
  OBS
    LAYER M1 ;
      RECT 0.1960 0.0350 0.2100 0.1330 ;
    LAYER M0 ;
      RECT 0.0515 0.0400 0.1585 0.0520 ;
      RECT 0.1775 0.0400 0.2635 0.0520 ;
      RECT 0.1355 0.1160 0.2180 0.1280 ;
    LAYER V0 ;
      RECT 0.1960 0.0400 0.2100 0.0520 ;
      RECT 0.1960 0.1160 0.2100 0.1280 ;
  END
END gt2_7t_oa31_x1_w31_lvt

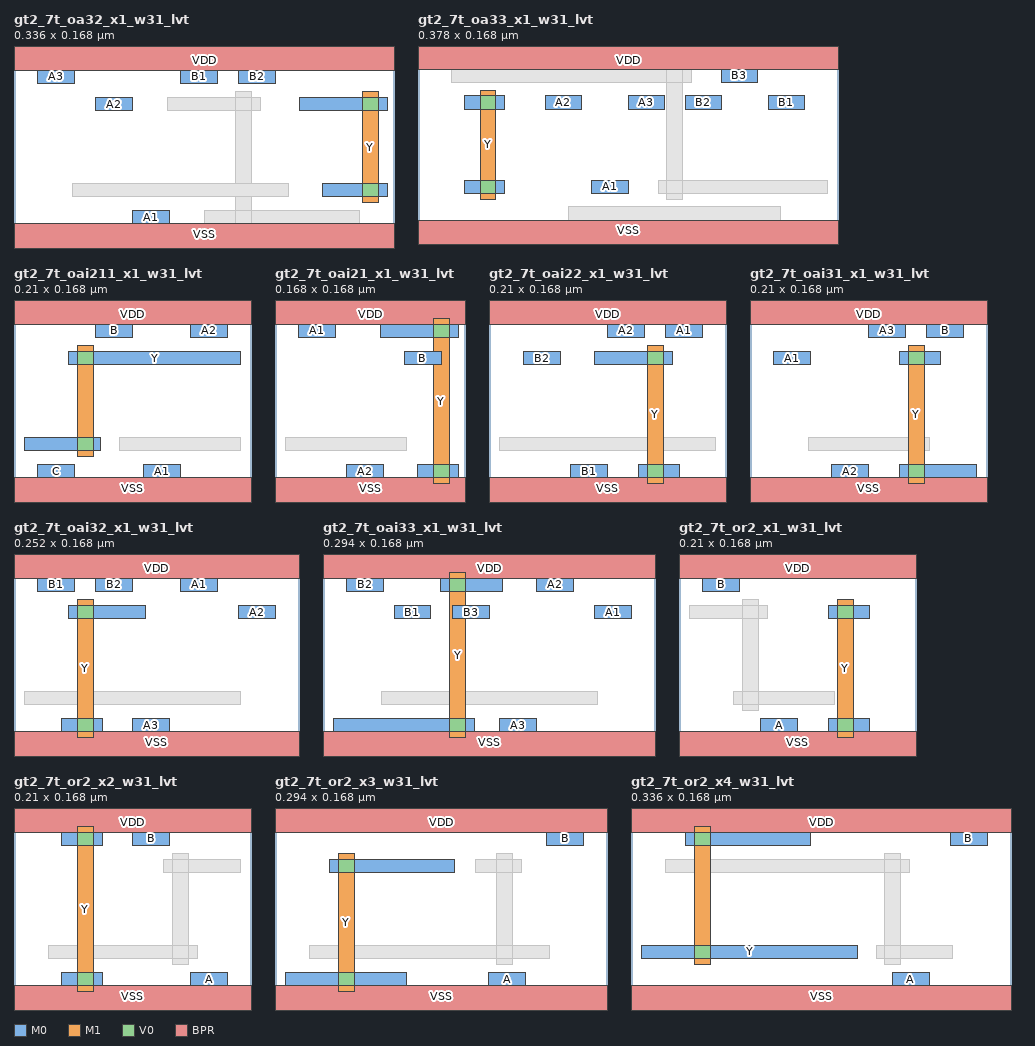
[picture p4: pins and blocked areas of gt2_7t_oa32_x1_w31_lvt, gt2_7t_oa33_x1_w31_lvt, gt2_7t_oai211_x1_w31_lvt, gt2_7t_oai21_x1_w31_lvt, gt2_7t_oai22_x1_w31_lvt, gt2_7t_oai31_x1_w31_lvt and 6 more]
MACRO gt2_7t_oa32_x1_w31_lvt
  CLASS CORE ;
  ORIGIN 0 0 ;
  FOREIGN gt2_6t_oa32_x1_w31_lvt 0 0 ;
  SIZE 0.3360 BY 0.1680 ;
  SYMMETRY X Y ;
  SITE gt2_7t ;
  PIN A1
    DIRECTION INPUT ;
    USE SIGNAL ;
    PORT
      LAYER M0 ;
        RECT 0.1050 0.0160 0.1375 0.0280 ;
    END
  END A1
  PIN A2
    DIRECTION INPUT ;
    USE SIGNAL ;
    PORT
      LAYER M0 ;
        RECT 0.0725 0.1160 0.1050 0.1280 ;
    END
  END A2
  PIN A3
    DIRECTION INPUT ;
    USE SIGNAL ;
    PORT
      LAYER M0 ;
        RECT 0.0210 0.1400 0.0535 0.1520 ;
    END
  END A3
  PIN B1
    DIRECTION INPUT ;
    USE SIGNAL ;
    PORT
      LAYER M0 ;
        RECT 0.1470 0.1400 0.1795 0.1520 ;
    END
  END B1
  PIN B2
    DIRECTION INPUT ;
    USE SIGNAL ;
    PORT
      LAYER M0 ;
        RECT 0.1985 0.1400 0.2310 0.1520 ;
    END
  END B2
  PIN Y
    DIRECTION OUTPUT ;
    USE SIGNAL ;
    PORT
      LAYER M1 ;
        RECT 0.3080 0.0350 0.3220 0.1330 ;
      LAYER M0 ;
        RECT 0.2730 0.0400 0.3300 0.0520 ;
        RECT 0.2520 0.1160 0.3300 0.1280 ;
      LAYER V0 ;
        RECT 0.3080 0.0400 0.3220 0.0520 ;
        RECT 0.3080 0.1160 0.3220 0.1280 ;
    END
  END Y
  PIN VDD
    DIRECTION INOUT ;
    USE POWER ;
    SHAPE ABUTMENT ;
    PORT
      LAYER BPR ;
        RECT 0.0000 0.1520 0.3360 0.1840 ;
    END
  END VDD
  PIN VSS
    DIRECTION INOUT ;
    USE GROUND ;
    SHAPE ABUTMENT ;
    PORT
      LAYER BPR ;
        RECT 0.0000 -0.0160 0.3360 0.0160 ;
    END
  END VSS
  OBS
    LAYER M1 ;
      RECT 0.1960 0.0110 0.2100 0.1330 ;
    LAYER M0 ;
      RECT 0.1680 0.0160 0.3055 0.0280 ;
      RECT 0.1355 0.1160 0.2180 0.1280 ;
      RECT 0.0515 0.0400 0.2425 0.0520 ;
    LAYER V0 ;
      RECT 0.1960 0.0160 0.2100 0.0280 ;
      RECT 0.1960 0.1160 0.2100 0.1280 ;
  END
END gt2_7t_oa32_x1_w31_lvt

MACRO gt2_7t_oa33_x1_w31_lvt
  CLASS CORE ;
  ORIGIN 0 0 ;
  FOREIGN gt2_6t_oa33_x1_w31_lvt 0 0 ;
  SIZE 0.3780 BY 0.1680 ;
  SYMMETRY X Y ;
  SITE gt2_7t ;
  PIN A1
    DIRECTION INPUT ;
    USE SIGNAL ;
    PORT
      LAYER M0 ;
        RECT 0.1565 0.0400 0.1890 0.0520 ;
    END
  END A1
  PIN A2
    DIRECTION INPUT ;
    USE SIGNAL ;
    PORT
      LAYER M0 ;
        RECT 0.1145 0.1160 0.1470 0.1280 ;
    END
  END A2
  PIN A3
    DIRECTION INPUT ;
    USE SIGNAL ;
    PORT
      LAYER M0 ;
        RECT 0.1890 0.1160 0.2215 0.1280 ;
    END
  END A3
  PIN B1
    DIRECTION INPUT ;
    USE SIGNAL ;
    PORT
      LAYER M0 ;
        RECT 0.3150 0.1160 0.3475 0.1280 ;
    END
  END B1
  PIN B2
    DIRECTION INPUT ;
    USE SIGNAL ;
    PORT
      LAYER M0 ;
        RECT 0.2405 0.1160 0.2730 0.1280 ;
    END
  END B2
  PIN B3
    DIRECTION INPUT ;
    USE SIGNAL ;
    PORT
      LAYER M0 ;
        RECT 0.2730 0.1400 0.3055 0.1520 ;
    END
  END B3
  PIN Y
    DIRECTION OUTPUT ;
    USE SIGNAL ;
    PORT
      LAYER M1 ;
        RECT 0.0560 0.0350 0.0700 0.1330 ;
      LAYER M0 ;
        RECT 0.0420 0.0400 0.0780 0.0520 ;
        RECT 0.0420 0.1160 0.0780 0.1280 ;
      LAYER V0 ;
        RECT 0.0560 0.0400 0.0700 0.0520 ;
        RECT 0.0560 0.1160 0.0700 0.1280 ;
    END
  END Y
  PIN VDD
    DIRECTION INOUT ;
    USE POWER ;
    SHAPE ABUTMENT ;
    PORT
      LAYER BPR ;
        RECT 0.0000 0.1520 0.3780 0.1840 ;
    END
  END VDD
  PIN VSS
    DIRECTION INOUT ;
    USE GROUND ;
    SHAPE ABUTMENT ;
    PORT
      LAYER BPR ;
        RECT 0.0000 -0.0160 0.3780 0.0160 ;
    END
  END VSS
  OBS
    LAYER M1 ;
      RECT 0.2240 0.0350 0.2380 0.1570 ;
    LAYER M0 ;
      RECT 0.1355 0.0160 0.3265 0.0280 ;
      RECT 0.2160 0.0400 0.3685 0.0520 ;
      RECT 0.0305 0.1400 0.2460 0.1520 ;
    LAYER V0 ;
      RECT 0.2240 0.0400 0.2380 0.0520 ;
      RECT 0.2240 0.1400 0.2380 0.1520 ;
  END
END gt2_7t_oa33_x1_w31_lvt

MACRO gt2_7t_oai211_x1_w31_lvt
  CLASS CORE ;
  ORIGIN 0 0 ;
  FOREIGN gt2_6t_oai211_x1_w31_lvt 0 0 ;
  SIZE 0.2100 BY 0.1680 ;
  SYMMETRY X Y ;
  SITE gt2_7t ;
  PIN A1
    DIRECTION INPUT ;
    USE SIGNAL ;
    PORT
      LAYER M0 ;
        RECT 0.1145 0.0160 0.1470 0.0280 ;
    END
  END A1
  PIN A2
    DIRECTION INPUT ;
    USE SIGNAL ;
    PORT
      LAYER M0 ;
        RECT 0.1565 0.1400 0.1890 0.1520 ;
    END
  END A2
  PIN B
    DIRECTION INPUT ;
    USE SIGNAL ;
    PORT
      LAYER M0 ;
        RECT 0.0725 0.1400 0.1050 0.1520 ;
    END
  END B
  PIN C
    DIRECTION INPUT ;
    USE SIGNAL ;
    PORT
      LAYER M0 ;
        RECT 0.0210 0.0160 0.0535 0.0280 ;
    END
  END C
  PIN Y
    DIRECTION OUTPUT ;
    USE SIGNAL ;
    PORT
      LAYER M1 ;
        RECT 0.0560 0.0350 0.0700 0.1330 ;
      LAYER M0 ;
        RECT 0.0095 0.0400 0.0765 0.0520 ;
        RECT 0.0480 0.1160 0.2005 0.1280 ;
      LAYER V0 ;
        RECT 0.0560 0.0400 0.0700 0.0520 ;
        RECT 0.0560 0.1160 0.0700 0.1280 ;
    END
  END Y
  PIN VDD
    DIRECTION INOUT ;
    USE POWER ;
    SHAPE ABUTMENT ;
    PORT
      LAYER BPR ;
        RECT 0.0000 0.1520 0.2100 0.1840 ;
    END
  END VDD
  PIN VSS
    DIRECTION INOUT ;
    USE GROUND ;
    SHAPE ABUTMENT ;
    PORT
      LAYER BPR ;
        RECT 0.0000 -0.0160 0.2100 0.0160 ;
    END
  END VSS
  OBS
    LAYER M0 ;
      RECT 0.0935 0.0400 0.2005 0.0520 ;
  END
END gt2_7t_oai211_x1_w31_lvt

MACRO gt2_7t_oai21_x1_w31_lvt
  CLASS CORE ;
  ORIGIN 0 0 ;
  FOREIGN gt2_6t_oai21_x1_w31_lvt 0 0 ;
  SIZE 0.1680 BY 0.1680 ;
  SYMMETRY X Y ;
  SITE gt2_7t ;
  PIN A1
    DIRECTION INPUT ;
    USE SIGNAL ;
    PORT
      LAYER M0 ;
        RECT 0.0210 0.1400 0.0535 0.1520 ;
    END
  END A1
  PIN A2
    DIRECTION INPUT ;
    USE SIGNAL ;
    PORT
      LAYER M0 ;
        RECT 0.0630 0.0160 0.0955 0.0280 ;
    END
  END A2
  PIN B
    DIRECTION INPUT ;
    USE SIGNAL ;
    PORT
      LAYER M0 ;
        RECT 0.1145 0.1160 0.1470 0.1280 ;
    END
  END B
  PIN Y
    DIRECTION OUTPUT ;
    USE SIGNAL ;
    PORT
      LAYER M1 ;
        RECT 0.1400 0.0110 0.1540 0.1570 ;
      LAYER M0 ;
        RECT 0.1260 0.0160 0.1620 0.0280 ;
        RECT 0.0935 0.1400 0.1620 0.1520 ;
      LAYER V0 ;
        RECT 0.1400 0.0160 0.1540 0.0280 ;
        RECT 0.1400 0.1400 0.1540 0.1520 ;
    END
  END Y
  PIN VDD
    DIRECTION INOUT ;
    USE POWER ;
    SHAPE ABUTMENT ;
    PORT
      LAYER BPR ;
        RECT 0.0000 0.1520 0.1680 0.1840 ;
    END
  END VDD
  PIN VSS
    DIRECTION INOUT ;
    USE GROUND ;
    SHAPE ABUTMENT ;
    PORT
      LAYER BPR ;
        RECT 0.0000 -0.0160 0.1680 0.0160 ;
    END
  END VSS
  OBS
    LAYER M0 ;
      RECT 0.0095 0.0400 0.1165 0.0520 ;
  END
END gt2_7t_oai21_x1_w31_lvt

MACRO gt2_7t_oai22_x1_w31_lvt
  CLASS CORE ;
  ORIGIN 0 0 ;
  FOREIGN gt2_6t_oai22_x1_w31_lvt 0 0 ;
  SIZE 0.2100 BY 0.1680 ;
  SYMMETRY X Y ;
  SITE gt2_7t ;
  PIN A1
    DIRECTION INPUT ;
    USE SIGNAL ;
    PORT
      LAYER M0 ;
        RECT 0.1565 0.1400 0.1890 0.1520 ;
    END
  END A1
  PIN A2
    DIRECTION INPUT ;
    USE SIGNAL ;
    PORT
      LAYER M0 ;
        RECT 0.1050 0.1400 0.1375 0.1520 ;
    END
  END A2
  PIN B1
    DIRECTION INPUT ;
    USE SIGNAL ;
    PORT
      LAYER M0 ;
        RECT 0.0725 0.0160 0.1050 0.0280 ;
    END
  END B1
  PIN B2
    DIRECTION INPUT ;
    USE SIGNAL ;
    PORT
      LAYER M0 ;
        RECT 0.0305 0.1160 0.0630 0.1280 ;
    END
  END B2
  PIN Y
    DIRECTION OUTPUT ;
    USE SIGNAL ;
    PORT
      LAYER M1 ;
        RECT 0.1400 0.0110 0.1540 0.1330 ;
      LAYER M0 ;
        RECT 0.1320 0.0160 0.1680 0.0280 ;
        RECT 0.0935 0.1160 0.1620 0.1280 ;
      LAYER V0 ;
        RECT 0.1400 0.0160 0.1540 0.0280 ;
        RECT 0.1400 0.1160 0.1540 0.1280 ;
    END
  END Y
  PIN VDD
    DIRECTION INOUT ;
    USE POWER ;
    SHAPE ABUTMENT ;
    PORT
      LAYER BPR ;
        RECT 0.0000 0.1520 0.2100 0.1840 ;
    END
  END VDD
  PIN VSS
    DIRECTION INOUT ;
    USE GROUND ;
    SHAPE ABUTMENT ;
    PORT
      LAYER BPR ;
        RECT 0.0000 -0.0160 0.2100 0.0160 ;
    END
  END VSS
  OBS
    LAYER M0 ;
      RECT 0.0095 0.0400 0.2005 0.0520 ;
  END
END gt2_7t_oai22_x1_w31_lvt

MACRO gt2_7t_oai31_x1_w31_lvt
  CLASS CORE ;
  ORIGIN 0 0 ;
  FOREIGN gt2_6t_oai31_x1_w31_lvt 0 0 ;
  SIZE 0.2100 BY 0.1680 ;
  SYMMETRY X Y ;
  SITE gt2_7t ;
  PIN A1
    DIRECTION INPUT ;
    USE SIGNAL ;
    PORT
      LAYER M0 ;
        RECT 0.0210 0.1160 0.0535 0.1280 ;
    END
  END A1
  PIN A2
    DIRECTION INPUT ;
    USE SIGNAL ;
    PORT
      LAYER M0 ;
        RECT 0.0725 0.0160 0.1050 0.0280 ;
    END
  END A2
  PIN A3
    DIRECTION INPUT ;
    USE SIGNAL ;
    PORT
      LAYER M0 ;
        RECT 0.1050 0.1400 0.1375 0.1520 ;
    END
  END A3
  PIN B
    DIRECTION INPUT ;
    USE SIGNAL ;
    PORT
      LAYER M0 ;
        RECT 0.1565 0.1400 0.1890 0.1520 ;
    END
  END B
  PIN Y
    DIRECTION OUTPUT ;
    USE SIGNAL ;
    PORT
      LAYER M1 ;
        RECT 0.1400 0.0110 0.1540 0.1330 ;
      LAYER M0 ;
        RECT 0.1320 0.0160 0.2005 0.0280 ;
        RECT 0.1320 0.1160 0.1680 0.1280 ;
      LAYER V0 ;
        RECT 0.1400 0.0160 0.1540 0.0280 ;
        RECT 0.1400 0.1160 0.1540 0.1280 ;
    END
  END Y
  PIN VDD
    DIRECTION INOUT ;
    USE POWER ;
    SHAPE ABUTMENT ;
    PORT
      LAYER BPR ;
        RECT 0.0000 0.1520 0.2100 0.1840 ;
    END
  END VDD
  PIN VSS
    DIRECTION INOUT ;
    USE GROUND ;
    SHAPE ABUTMENT ;
    PORT
      LAYER BPR ;
        RECT 0.0000 -0.0160 0.2100 0.0160 ;
    END
  END VSS
  OBS
    LAYER M0 ;
      RECT 0.0515 0.0400 0.1585 0.0520 ;
  END
END gt2_7t_oai31_x1_w31_lvt

MACRO gt2_7t_oai32_x1_w31_lvt
  CLASS CORE ;
  ORIGIN 0 0 ;
  FOREIGN gt2_6t_oai32_x1_w31_lvt 0 0 ;
  SIZE 0.2520 BY 0.1680 ;
  SYMMETRY X Y ;
  SITE gt2_7t ;
  PIN A1
    DIRECTION INPUT ;
    USE SIGNAL ;
    PORT
      LAYER M0 ;
        RECT 0.1470 0.1400 0.1795 0.1520 ;
    END
  END A1
  PIN A2
    DIRECTION INPUT ;
    USE SIGNAL ;
    PORT
      LAYER M0 ;
        RECT 0.1985 0.1160 0.2310 0.1280 ;
    END
  END A2
  PIN A3
    DIRECTION INPUT ;
    USE SIGNAL ;
    PORT
      LAYER M0 ;
        RECT 0.1050 0.0160 0.1375 0.0280 ;
    END
  END A3
  PIN B1
    DIRECTION INPUT ;
    USE SIGNAL ;
    PORT
      LAYER M0 ;
        RECT 0.0210 0.1400 0.0535 0.1520 ;
    END
  END B1
  PIN B2
    DIRECTION INPUT ;
    USE SIGNAL ;
    PORT
      LAYER M0 ;
        RECT 0.0725 0.1400 0.1050 0.1520 ;
    END
  END B2
  PIN Y
    DIRECTION OUTPUT ;
    USE SIGNAL ;
    PORT
      LAYER M1 ;
        RECT 0.0560 0.0110 0.0700 0.1330 ;
      LAYER M0 ;
        RECT 0.0420 0.0160 0.0780 0.0280 ;
        RECT 0.0480 0.1160 0.1165 0.1280 ;
      LAYER V0 ;
        RECT 0.0560 0.0160 0.0700 0.0280 ;
        RECT 0.0560 0.1160 0.0700 0.1280 ;
    END
  END Y
  PIN VDD
    DIRECTION INOUT ;
    USE POWER ;
    SHAPE ABUTMENT ;
    PORT
      LAYER BPR ;
        RECT 0.0000 0.1520 0.2520 0.1840 ;
    END
  END VDD
  PIN VSS
    DIRECTION INOUT ;
    USE GROUND ;
    SHAPE ABUTMENT ;
    PORT
      LAYER BPR ;
        RECT 0.0000 -0.0160 0.2520 0.0160 ;
    END
  END VSS
  OBS
    LAYER M0 ;
      RECT 0.0095 0.0400 0.2005 0.0520 ;
  END
END gt2_7t_oai32_x1_w31_lvt

MACRO gt2_7t_oai33_x1_w31_lvt
  CLASS CORE ;
  ORIGIN 0 0 ;
  FOREIGN gt2_6t_oai33_x1_w31_lvt 0 0 ;
  SIZE 0.2940 BY 0.1680 ;
  SYMMETRY X Y ;
  SITE gt2_7t ;
  PIN A1
    DIRECTION INPUT ;
    USE SIGNAL ;
    PORT
      LAYER M0 ;
        RECT 0.2405 0.1160 0.2730 0.1280 ;
    END
  END A1
  PIN A2
    DIRECTION INPUT ;
    USE SIGNAL ;
    PORT
      LAYER M0 ;
        RECT 0.1890 0.1400 0.2215 0.1520 ;
    END
  END A2
  PIN A3
    DIRECTION INPUT ;
    USE SIGNAL ;
    PORT
      LAYER M0 ;
        RECT 0.1565 0.0160 0.1890 0.0280 ;
    END
  END A3
  PIN B1
    DIRECTION INPUT ;
    USE SIGNAL ;
    PORT
      LAYER M0 ;
        RECT 0.0630 0.1160 0.0950 0.1280 ;
    END
  END B1
  PIN B2
    DIRECTION INPUT ;
    USE SIGNAL ;
    PORT
      LAYER M0 ;
        RECT 0.0210 0.1400 0.0535 0.1520 ;
    END
  END B2
  PIN B3
    DIRECTION INPUT ;
    USE SIGNAL ;
    PORT
      LAYER M0 ;
        RECT 0.1145 0.1160 0.1470 0.1280 ;
    END
  END B3
  PIN Y
    DIRECTION OUTPUT ;
    USE SIGNAL ;
    PORT
      LAYER M1 ;
        RECT 0.1120 0.0110 0.1260 0.1570 ;
      LAYER M0 ;
        RECT 0.0095 0.0160 0.1340 0.0280 ;
        RECT 0.1040 0.1400 0.1585 0.1520 ;
      LAYER V0 ;
        RECT 0.1120 0.0160 0.1260 0.0280 ;
        RECT 0.1120 0.1400 0.1260 0.1520 ;
    END
  END Y
  PIN VDD
    DIRECTION INOUT ;
    USE POWER ;
    SHAPE ABUTMENT ;
    PORT
      LAYER BPR ;
        RECT 0.0000 0.1520 0.2940 0.1840 ;
    END
  END VDD
  PIN VSS
    DIRECTION INOUT ;
    USE GROUND ;
    SHAPE ABUTMENT ;
    PORT
      LAYER BPR ;
        RECT 0.0000 -0.0160 0.2940 0.0160 ;
    END
  END VSS
  OBS
    LAYER M0 ;
      RECT 0.0515 0.0400 0.2425 0.0520 ;
  END
END gt2_7t_oai33_x1_w31_lvt

MACRO gt2_7t_or2_x1_w31_lvt
  CLASS CORE ;
  ORIGIN 0 0 ;
  FOREIGN gt2_6t_or2_x1_w31_lvt 0 0 ;
  SIZE 0.2100 BY 0.1680 ;
  SYMMETRY X Y ;
  SITE gt2_7t ;
  PIN A
    DIRECTION INPUT ;
    USE SIGNAL ;
    PORT
      LAYER M0 ;
        RECT 0.0725 0.0160 0.1050 0.0280 ;
    END
  END A
  PIN B
    DIRECTION INPUT ;
    USE SIGNAL ;
    PORT
      LAYER M0 ;
        RECT 0.0210 0.1400 0.0535 0.1520 ;
    END
  END B
  PIN Y
    DIRECTION OUTPUT ;
    USE SIGNAL ;
    PORT
      LAYER M1 ;
        RECT 0.1400 0.0110 0.1540 0.1330 ;
      LAYER M0 ;
        RECT 0.1320 0.0160 0.1680 0.0280 ;
        RECT 0.1320 0.1160 0.1680 0.1280 ;
      LAYER V0 ;
        RECT 0.1400 0.0160 0.1540 0.0280 ;
        RECT 0.1400 0.1160 0.1540 0.1280 ;
    END
  END Y
  PIN VDD
    DIRECTION INOUT ;
    USE POWER ;
    SHAPE ABUTMENT ;
    PORT
      LAYER BPR ;
        RECT 0.0000 0.1520 0.2100 0.1840 ;
    END
  END VDD
  PIN VSS
    DIRECTION INOUT ;
    USE GROUND ;
    SHAPE ABUTMENT ;
    PORT
      LAYER BPR ;
        RECT 0.0000 -0.0160 0.2100 0.0160 ;
    END
  END VSS
  OBS
    LAYER M1 ;
      RECT 0.0560 0.0350 0.0700 0.1330 ;
    LAYER M0 ;
      RECT 0.0480 0.0400 0.1375 0.0520 ;
      RECT 0.0095 0.1160 0.0780 0.1280 ;
    LAYER V0 ;
      RECT 0.0560 0.0400 0.0700 0.0520 ;
      RECT 0.0560 0.1160 0.0700 0.1280 ;
  END
END gt2_7t_or2_x1_w31_lvt

MACRO gt2_7t_or2_x2_w31_lvt
  CLASS CORE ;
  ORIGIN 0 0 ;
  FOREIGN gt2_6t_or2_x2_w31_lvt 0 0 ;
  SIZE 0.2100 BY 0.1680 ;
  SYMMETRY X Y ;
  SITE gt2_7t ;
  PIN A
    DIRECTION INPUT ;
    USE SIGNAL ;
    PORT
      LAYER M0 ;
        RECT 0.1565 0.0160 0.1890 0.0280 ;
    END
  END A
  PIN B
    DIRECTION INPUT ;
    USE SIGNAL ;
    PORT
      LAYER M0 ;
        RECT 0.1050 0.1400 0.1375 0.1520 ;
    END
  END B
  PIN Y
    DIRECTION OUTPUT ;
    USE SIGNAL ;
    PORT
      LAYER M1 ;
        RECT 0.0560 0.0110 0.0700 0.1570 ;
      LAYER M0 ;
        RECT 0.0420 0.0160 0.0780 0.0280 ;
        RECT 0.0420 0.1400 0.0780 0.1520 ;
      LAYER V0 ;
        RECT 0.0560 0.0160 0.0700 0.0280 ;
        RECT 0.0560 0.1400 0.0700 0.1520 ;
    END
  END Y
  PIN VDD
    DIRECTION INOUT ;
    USE POWER ;
    SHAPE ABUTMENT ;
    PORT
      LAYER BPR ;
        RECT 0.0000 0.1520 0.2100 0.1840 ;
    END
  END VDD
  PIN VSS
    DIRECTION INOUT ;
    USE GROUND ;
    SHAPE ABUTMENT ;
    PORT
      LAYER BPR ;
        RECT 0.0000 -0.0160 0.2100 0.0160 ;
    END
  END VSS
  OBS
    LAYER M1 ;
      RECT 0.1400 0.0350 0.1540 0.1330 ;
    LAYER M0 ;
      RECT 0.0305 0.0400 0.1620 0.0520 ;
      RECT 0.1320 0.1160 0.2005 0.1280 ;
    LAYER V0 ;
      RECT 0.1400 0.0400 0.1540 0.0520 ;
      RECT 0.1400 0.1160 0.1540 0.1280 ;
  END
END gt2_7t_or2_x2_w31_lvt

MACRO gt2_7t_or2_x3_w31_lvt
  CLASS CORE ;
  ORIGIN 0 0 ;
  FOREIGN gt2_6t_or2_x3_w31_lvt 0 0 ;
  SIZE 0.2940 BY 0.1680 ;
  SYMMETRY X Y ;
  SITE gt2_7t ;
  PIN A
    DIRECTION INPUT ;
    USE SIGNAL ;
    PORT
      LAYER M0 ;
        RECT 0.1890 0.0160 0.2215 0.0280 ;
    END
  END A
  PIN B
    DIRECTION INPUT ;
    USE SIGNAL ;
    PORT
      LAYER M0 ;
        RECT 0.2405 0.1400 0.2730 0.1520 ;
    END
  END B
  PIN Y
    DIRECTION OUTPUT ;
    USE SIGNAL ;
    PORT
      LAYER M1 ;
        RECT 0.0560 0.0110 0.0700 0.1330 ;
      LAYER M0 ;
        RECT 0.0095 0.0160 0.1165 0.0280 ;
        RECT 0.0480 0.1160 0.1585 0.1280 ;
      LAYER V0 ;
        RECT 0.0560 0.0160 0.0700 0.0280 ;
        RECT 0.0560 0.1160 0.0700 0.1280 ;
    END
  END Y
  PIN VDD
    DIRECTION INOUT ;
    USE POWER ;
    SHAPE ABUTMENT ;
    PORT
      LAYER BPR ;
        RECT 0.0000 0.1520 0.2940 0.1840 ;
    END
  END VDD
  PIN VSS
    DIRECTION INOUT ;
    USE GROUND ;
    SHAPE ABUTMENT ;
    PORT
      LAYER BPR ;
        RECT 0.0000 -0.0160 0.2940 0.0160 ;
    END
  END VSS
  OBS
    LAYER M1 ;
      RECT 0.1960 0.0350 0.2100 0.1330 ;
    LAYER M0 ;
      RECT 0.0305 0.0400 0.2425 0.0520 ;
      RECT 0.1775 0.1160 0.2180 0.1280 ;
    LAYER V0 ;
      RECT 0.1960 0.0400 0.2100 0.0520 ;
      RECT 0.1960 0.1160 0.2100 0.1280 ;
  END
END gt2_7t_or2_x3_w31_lvt

MACRO gt2_7t_or2_x4_w31_lvt
  CLASS CORE ;
  ORIGIN 0 0 ;
  FOREIGN gt2_6t_or2_x4_w31_lvt 0 0 ;
  SIZE 0.3360 BY 0.1680 ;
  SYMMETRY X Y ;
  SITE gt2_7t ;
  PIN A
    DIRECTION INPUT ;
    USE SIGNAL ;
    PORT
      LAYER M0 ;
        RECT 0.2310 0.0160 0.2635 0.0280 ;
    END
  END A
  PIN B
    DIRECTION INPUT ;
    USE SIGNAL ;
    PORT
      LAYER M0 ;
        RECT 0.2825 0.1400 0.3150 0.1520 ;
    END
  END B
  PIN Y
    DIRECTION OUTPUT ;
    USE SIGNAL ;
    PORT
      LAYER M1 ;
        RECT 0.0560 0.0350 0.0700 0.1570 ;
      LAYER M0 ;
        RECT 0.0095 0.0400 0.2005 0.0520 ;
        RECT 0.0480 0.1400 0.1585 0.1520 ;
      LAYER V0 ;
        RECT 0.0560 0.0400 0.0700 0.0520 ;
        RECT 0.0560 0.1400 0.0700 0.1520 ;
    END
  END Y
  PIN VDD
    DIRECTION INOUT ;
    USE POWER ;
    SHAPE ABUTMENT ;
    PORT
      LAYER BPR ;
        RECT 0.0000 0.1520 0.3360 0.1840 ;
    END
  END VDD
  PIN VSS
    DIRECTION INOUT ;
    USE GROUND ;
    SHAPE ABUTMENT ;
    PORT
      LAYER BPR ;
        RECT 0.0000 -0.0160 0.3360 0.0160 ;
    END
  END VSS
  OBS
    LAYER M1 ;
      RECT 0.2240 0.0350 0.2380 0.1330 ;
    LAYER M0 ;
      RECT 0.2175 0.0400 0.2845 0.0520 ;
      RECT 0.0305 0.1160 0.2460 0.1280 ;
    LAYER V0 ;
      RECT 0.2240 0.0400 0.2380 0.0520 ;
      RECT 0.2240 0.1160 0.2380 0.1280 ;
  END
END gt2_7t_or2_x4_w31_lvt

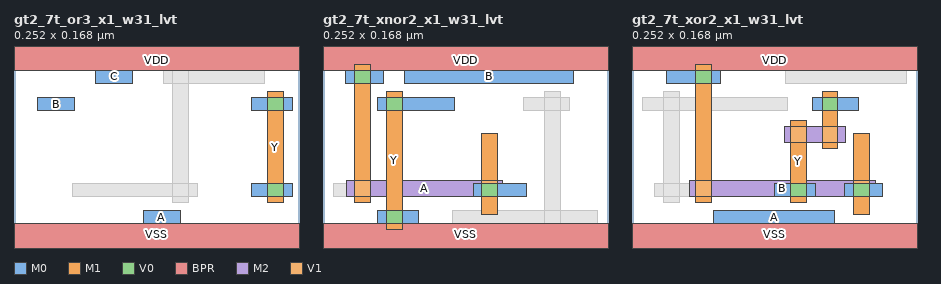
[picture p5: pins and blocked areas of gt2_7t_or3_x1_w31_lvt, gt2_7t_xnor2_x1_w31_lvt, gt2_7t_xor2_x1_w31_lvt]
MACRO gt2_7t_or3_x1_w31_lvt
  CLASS CORE ;
  ORIGIN 0 0 ;
  FOREIGN gt2_6t_or3_x1_w31_lvt 0 0 ;
  SIZE 0.2520 BY 0.1680 ;
  SYMMETRY X Y ;
  SITE gt2_7t ;
  PIN A
    DIRECTION INPUT ;
    USE SIGNAL ;
    PORT
      LAYER M0 ;
        RECT 0.1145 0.0160 0.1470 0.0280 ;
    END
  END A
  PIN B
    DIRECTION INPUT ;
    USE SIGNAL ;
    PORT
      LAYER M0 ;
        RECT 0.0210 0.1160 0.0535 0.1280 ;
    END
  END B
  PIN C
    DIRECTION INPUT ;
    USE SIGNAL ;
    PORT
      LAYER M0 ;
        RECT 0.0725 0.1400 0.1050 0.1520 ;
    END
  END C
  PIN Y
    DIRECTION OUTPUT ;
    USE SIGNAL ;
    PORT
      LAYER M1 ;
        RECT 0.2240 0.0350 0.2380 0.1330 ;
      LAYER M0 ;
        RECT 0.2100 0.0400 0.2460 0.0520 ;
        RECT 0.2100 0.1160 0.2460 0.1280 ;
      LAYER V0 ;
        RECT 0.2240 0.0400 0.2380 0.0520 ;
        RECT 0.2240 0.1160 0.2380 0.1280 ;
    END
  END Y
  PIN VDD
    DIRECTION INOUT ;
    USE POWER ;
    SHAPE ABUTMENT ;
    PORT
      LAYER BPR ;
        RECT 0.0000 0.1520 0.2520 0.1840 ;
    END
  END VDD
  PIN VSS
    DIRECTION INOUT ;
    USE GROUND ;
    SHAPE ABUTMENT ;
    PORT
      LAYER BPR ;
        RECT 0.0000 -0.0160 0.2520 0.0160 ;
    END
  END VSS
  OBS
    LAYER M1 ;
      RECT 0.1400 0.0350 0.1540 0.1570 ;
    LAYER M0 ;
      RECT 0.0515 0.0400 0.1620 0.0520 ;
      RECT 0.1320 0.1400 0.2215 0.1520 ;
    LAYER V0 ;
      RECT 0.1400 0.0400 0.1540 0.0520 ;
      RECT 0.1400 0.1400 0.1540 0.1520 ;
  END
END gt2_7t_or3_x1_w31_lvt

MACRO gt2_7t_xnor2_x1_w31_lvt
  CLASS CORE ;
  ORIGIN 0 0 ;
  FOREIGN gt2_6t_xnor2_x1_w31_lvt 0 0 ;
  SIZE 0.2520 BY 0.1680 ;
  SYMMETRY X Y ;
  SITE gt2_7t ;
  PIN A
    DIRECTION INPUT ;
    USE SIGNAL ;
    PORT
      LAYER M2 ;
        RECT 0.0210 0.0400 0.1590 0.0540 ;
      LAYER M1 ;
        RECT 0.1400 0.0240 0.1540 0.0960 ;
        RECT 0.0280 0.0350 0.0420 0.1570 ;
      LAYER M0 ;
        RECT 0.1335 0.0400 0.1795 0.0520 ;
        RECT 0.0200 0.1400 0.0535 0.1520 ;
      LAYER V1 ;
        RECT 0.0280 0.0400 0.0420 0.0540 ;
        RECT 0.1400 0.0400 0.1540 0.0540 ;
      LAYER V0 ;
        RECT 0.1400 0.0400 0.1540 0.0520 ;
        RECT 0.0280 0.1400 0.0420 0.1520 ;
    END
  END A
  PIN B
    DIRECTION INPUT ;
    USE SIGNAL ;
    PORT
      LAYER M0 ;
        RECT 0.0725 0.1400 0.2215 0.1520 ;
    END
  END B
  PIN Y
    DIRECTION OUTPUT ;
    USE SIGNAL ;
    PORT
      LAYER M1 ;
        RECT 0.0560 0.0110 0.0700 0.1330 ;
      LAYER M0 ;
        RECT 0.0480 0.0160 0.0840 0.0280 ;
        RECT 0.0480 0.1160 0.1165 0.1280 ;
      LAYER V0 ;
        RECT 0.0560 0.0160 0.0700 0.0280 ;
        RECT 0.0560 0.1160 0.0700 0.1280 ;
    END
  END Y
  PIN VDD
    DIRECTION INOUT ;
    USE POWER ;
    SHAPE ABUTMENT ;
    PORT
      LAYER BPR ;
        RECT 0.0000 0.1520 0.2520 0.1840 ;
    END
  END VDD
  PIN VSS
    DIRECTION INOUT ;
    USE GROUND ;
    SHAPE ABUTMENT ;
    PORT
      LAYER BPR ;
        RECT 0.0000 -0.0160 0.2520 0.0160 ;
    END
  END VSS
  OBS
    LAYER M1 ;
      RECT 0.1960 0.0110 0.2100 0.1330 ;
    LAYER M0 ;
      RECT 0.0095 0.0400 0.1165 0.0520 ;
      RECT 0.1145 0.0160 0.2425 0.0280 ;
      RECT 0.1775 0.1160 0.2180 0.1280 ;
    LAYER V0 ;
      RECT 0.1960 0.0160 0.2100 0.0280 ;
      RECT 0.1960 0.1160 0.2100 0.1280 ;
  END
END gt2_7t_xnor2_x1_w31_lvt

MACRO gt2_7t_xor2_x1_w31_lvt
  CLASS CORE ;
  ORIGIN 0 0 ;
  FOREIGN gt2_6t_xor2_x1_w31_lvt 0 0 ;
  SIZE 0.2520 BY 0.1680 ;
  SYMMETRY X Y ;
  SITE gt2_7t ;
  PIN A
    DIRECTION INPUT ;
    USE SIGNAL ;
    PORT
      LAYER M0 ;
        RECT 0.0725 0.0160 0.1790 0.0280 ;
    END
  END A
  PIN B
    DIRECTION INPUT ;
    USE SIGNAL ;
    PORT
      LAYER M2 ;
        RECT 0.0510 0.0400 0.2150 0.0540 ;
      LAYER M1 ;
        RECT 0.1960 0.0240 0.2100 0.0960 ;
        RECT 0.0560 0.0350 0.0700 0.1570 ;
      LAYER M0 ;
        RECT 0.1880 0.0400 0.2215 0.0520 ;
        RECT 0.0305 0.1400 0.0780 0.1520 ;
      LAYER V1 ;
        RECT 0.0560 0.0400 0.0700 0.0540 ;
        RECT 0.1960 0.0400 0.2100 0.0540 ;
      LAYER V0 ;
        RECT 0.1960 0.0400 0.2100 0.0520 ;
        RECT 0.0560 0.1400 0.0700 0.1520 ;
    END
  END B
  PIN Y
    DIRECTION OUTPUT ;
    USE SIGNAL ;
    PORT
      LAYER M2 ;
        RECT 0.1350 0.0880 0.1890 0.1020 ;
      LAYER M1 ;
        RECT 0.1400 0.0350 0.1540 0.1070 ;
        RECT 0.1680 0.0830 0.1820 0.1330 ;
      LAYER M0 ;
        RECT 0.1260 0.0400 0.1620 0.0520 ;
        RECT 0.1600 0.1160 0.2005 0.1280 ;
      LAYER V1 ;
        RECT 0.1400 0.0880 0.1540 0.1020 ;
        RECT 0.1680 0.0880 0.1820 0.1020 ;
      LAYER V0 ;
        RECT 0.1400 0.0400 0.1540 0.0520 ;
        RECT 0.1680 0.1160 0.1820 0.1280 ;
    END
  END Y
  PIN VDD
    DIRECTION INOUT ;
    USE POWER ;
    SHAPE ABUTMENT ;
    PORT
      LAYER BPR ;
        RECT 0.0000 0.1520 0.2520 0.1840 ;
    END
  END VDD
  PIN VSS
    DIRECTION INOUT ;
    USE GROUND ;
    SHAPE ABUTMENT ;
    PORT
      LAYER BPR ;
        RECT 0.0000 -0.0160 0.2520 0.0160 ;
    END
  END VSS
  OBS
    LAYER M1 ;
      RECT 0.0280 0.0350 0.0420 0.1330 ;
    LAYER M0 ;
      RECT 0.0200 0.0400 0.0745 0.0520 ;
      RECT 0.0095 0.1160 0.1375 0.1280 ;
      RECT 0.1355 0.1400 0.2425 0.1520 ;
    LAYER V0 ;
      RECT 0.0280 0.0400 0.0420 0.0520 ;
      RECT 0.0280 0.1160 0.0420 0.1280 ;
  END
END gt2_7t_xor2_x1_w31_lvt

END LIBRARY
